VERSION 5.7 ;
  NOWIREEXTENSIONATPIN ON ;
  DIVIDERCHAR "/" ;
  BUSBITCHARS "[]" ;
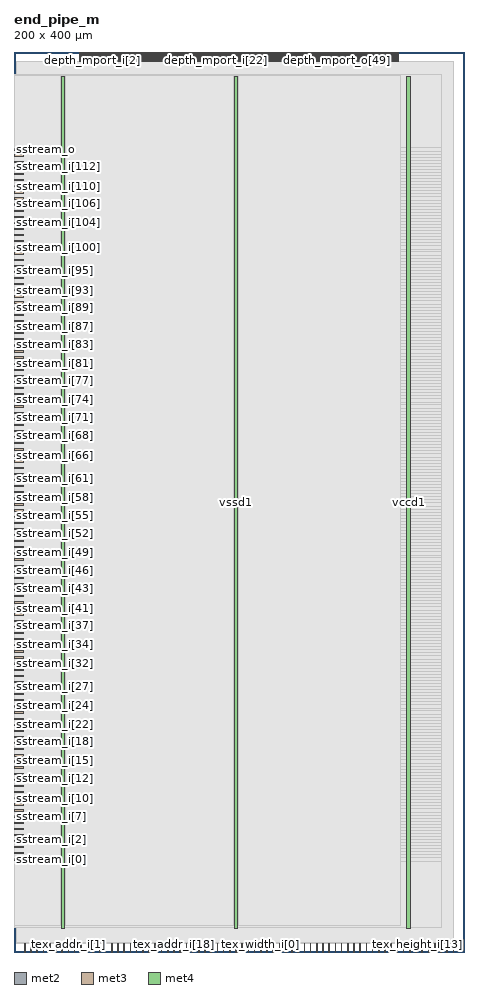
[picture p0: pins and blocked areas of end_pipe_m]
MACRO end_pipe_m
  CLASS BLOCK ;
  FOREIGN end_pipe_m ;
  ORIGIN 0.000 0.000 ;
  SIZE 200.000 BY 400.000 ;
  PIN busy_o
    DIRECTION OUTPUT TRISTATE ;
    USE SIGNAL ;
    ANTENNADIFFAREA 2.862000 ;
    PORT
      LAYER met2 ;
        RECT 15.730 0.000 16.010 4.000 ;
    END
  END busy_o
  PIN clk_i
    DIRECTION INPUT ;
    USE SIGNAL ;
    ANTENNAGATEAREA 0.852000 ;
    PORT
      LAYER met2 ;
        RECT 4.690 0.000 4.970 4.000 ;
    END
  END clk_i
  PIN depth_mport_i[0]
    DIRECTION INPUT ;
    USE SIGNAL ;
    ANTENNAGATEAREA 0.247500 ;
    PORT
      LAYER met2 ;
        RECT 29.070 396.000 29.350 400.000 ;
    END
  END depth_mport_i[0]
  PIN depth_mport_i[10]
    DIRECTION INPUT ;
    USE SIGNAL ;
    ANTENNAGATEAREA 0.495000 ;
    PORT
      LAYER met2 ;
        RECT 56.670 396.000 56.950 400.000 ;
    END
  END depth_mport_i[10]
  PIN depth_mport_i[11]
    DIRECTION INPUT ;
    USE SIGNAL ;
    ANTENNAGATEAREA 0.495000 ;
    PORT
      LAYER met2 ;
        RECT 59.430 396.000 59.710 400.000 ;
    END
  END depth_mport_i[11]
  PIN depth_mport_i[12]
    DIRECTION INPUT ;
    USE SIGNAL ;
    ANTENNAGATEAREA 0.495000 ;
    PORT
      LAYER met2 ;
        RECT 62.190 396.000 62.470 400.000 ;
    END
  END depth_mport_i[12]
  PIN depth_mport_i[13]
    DIRECTION INPUT ;
    USE SIGNAL ;
    ANTENNAGATEAREA 0.495000 ;
    PORT
      LAYER met2 ;
        RECT 64.950 396.000 65.230 400.000 ;
    END
  END depth_mport_i[13]
  PIN depth_mport_i[14]
    DIRECTION INPUT ;
    USE SIGNAL ;
    ANTENNAGATEAREA 0.495000 ;
    PORT
      LAYER met2 ;
        RECT 67.710 396.000 67.990 400.000 ;
    END
  END depth_mport_i[14]
  PIN depth_mport_i[15]
    DIRECTION INPUT ;
    USE SIGNAL ;
    ANTENNAGATEAREA 0.373500 ;
    PORT
      LAYER met2 ;
        RECT 70.470 396.000 70.750 400.000 ;
    END
  END depth_mport_i[15]
  PIN depth_mport_i[16]
    DIRECTION INPUT ;
    USE SIGNAL ;
    ANTENNAGATEAREA 0.495000 ;
    PORT
      LAYER met2 ;
        RECT 73.230 396.000 73.510 400.000 ;
    END
  END depth_mport_i[16]
  PIN depth_mport_i[17]
    DIRECTION INPUT ;
    USE SIGNAL ;
    ANTENNAGATEAREA 0.742500 ;
    PORT
      LAYER met2 ;
        RECT 75.990 396.000 76.270 400.000 ;
    END
  END depth_mport_i[17]
  PIN depth_mport_i[18]
    DIRECTION INPUT ;
    USE SIGNAL ;
    ANTENNAGATEAREA 0.742500 ;
    PORT
      LAYER met2 ;
        RECT 78.750 396.000 79.030 400.000 ;
    END
  END depth_mport_i[18]
  PIN depth_mport_i[19]
    DIRECTION INPUT ;
    USE SIGNAL ;
    ANTENNAGATEAREA 0.495000 ;
    PORT
      LAYER met2 ;
        RECT 81.510 396.000 81.790 400.000 ;
    END
  END depth_mport_i[19]
  PIN depth_mport_i[1]
    DIRECTION INPUT ;
    USE SIGNAL ;
    ANTENNAGATEAREA 0.373500 ;
    PORT
      LAYER met2 ;
        RECT 31.830 396.000 32.110 400.000 ;
    END
  END depth_mport_i[1]
  PIN depth_mport_i[20]
    DIRECTION INPUT ;
    USE SIGNAL ;
    ANTENNAGATEAREA 0.495000 ;
    PORT
      LAYER met2 ;
        RECT 84.270 396.000 84.550 400.000 ;
    END
  END depth_mport_i[20]
  PIN depth_mport_i[21]
    DIRECTION INPUT ;
    USE SIGNAL ;
    ANTENNAGATEAREA 0.495000 ;
    PORT
      LAYER met2 ;
        RECT 87.030 396.000 87.310 400.000 ;
    END
  END depth_mport_i[21]
  PIN depth_mport_i[22]
    DIRECTION INPUT ;
    USE SIGNAL ;
    ANTENNAGATEAREA 0.495000 ;
    PORT
      LAYER met2 ;
        RECT 89.790 396.000 90.070 400.000 ;
    END
  END depth_mport_i[22]
  PIN depth_mport_i[23]
    DIRECTION INPUT ;
    USE SIGNAL ;
    ANTENNAGATEAREA 0.495000 ;
    PORT
      LAYER met2 ;
        RECT 92.550 396.000 92.830 400.000 ;
    END
  END depth_mport_i[23]
  PIN depth_mport_i[24]
    DIRECTION INPUT ;
    USE SIGNAL ;
    ANTENNAGATEAREA 0.373500 ;
    PORT
      LAYER met2 ;
        RECT 95.310 396.000 95.590 400.000 ;
    END
  END depth_mport_i[24]
  PIN depth_mport_i[25]
    DIRECTION INPUT ;
    USE SIGNAL ;
    ANTENNAGATEAREA 0.495000 ;
    PORT
      LAYER met2 ;
        RECT 98.070 396.000 98.350 400.000 ;
    END
  END depth_mport_i[25]
  PIN depth_mport_i[26]
    DIRECTION INPUT ;
    USE SIGNAL ;
    ANTENNAGATEAREA 0.495000 ;
    PORT
      LAYER met2 ;
        RECT 100.830 396.000 101.110 400.000 ;
    END
  END depth_mport_i[26]
  PIN depth_mport_i[27]
    DIRECTION INPUT ;
    USE SIGNAL ;
    ANTENNAGATEAREA 0.495000 ;
    PORT
      LAYER met2 ;
        RECT 103.590 396.000 103.870 400.000 ;
    END
  END depth_mport_i[27]
  PIN depth_mport_i[28]
    DIRECTION INPUT ;
    USE SIGNAL ;
    ANTENNAGATEAREA 0.373500 ;
    PORT
      LAYER met2 ;
        RECT 106.350 396.000 106.630 400.000 ;
    END
  END depth_mport_i[28]
  PIN depth_mport_i[29]
    DIRECTION INPUT ;
    USE SIGNAL ;
    ANTENNAGATEAREA 0.990000 ;
    PORT
      LAYER met2 ;
        RECT 109.110 396.000 109.390 400.000 ;
    END
  END depth_mport_i[29]
  PIN depth_mport_i[2]
    DIRECTION INPUT ;
    USE SIGNAL ;
    ANTENNAGATEAREA 0.495000 ;
    PORT
      LAYER met2 ;
        RECT 34.590 396.000 34.870 400.000 ;
    END
  END depth_mport_i[2]
  PIN depth_mport_i[30]
    DIRECTION INPUT ;
    USE SIGNAL ;
    ANTENNAGATEAREA 0.990000 ;
    PORT
      LAYER met2 ;
        RECT 111.870 396.000 112.150 400.000 ;
    END
  END depth_mport_i[30]
  PIN depth_mport_i[31]
    DIRECTION INPUT ;
    USE SIGNAL ;
    ANTENNAGATEAREA 0.990000 ;
    PORT
      LAYER met2 ;
        RECT 114.630 396.000 114.910 400.000 ;
    END
  END depth_mport_i[31]
  PIN depth_mport_i[32]
    DIRECTION INPUT ;
    USE SIGNAL ;
    ANTENNAGATEAREA 0.742500 ;
    PORT
      LAYER met2 ;
        RECT 117.390 396.000 117.670 400.000 ;
    END
  END depth_mport_i[32]
  PIN depth_mport_i[33]
    DIRECTION INPUT ;
    USE SIGNAL ;
    PORT
      LAYER met2 ;
        RECT 120.150 396.000 120.430 400.000 ;
    END
  END depth_mport_i[33]
  PIN depth_mport_i[3]
    DIRECTION INPUT ;
    USE SIGNAL ;
    ANTENNAGATEAREA 0.495000 ;
    PORT
      LAYER met2 ;
        RECT 37.350 396.000 37.630 400.000 ;
    END
  END depth_mport_i[3]
  PIN depth_mport_i[4]
    DIRECTION INPUT ;
    USE SIGNAL ;
    ANTENNAGATEAREA 0.495000 ;
    PORT
      LAYER met2 ;
        RECT 40.110 396.000 40.390 400.000 ;
    END
  END depth_mport_i[4]
  PIN depth_mport_i[5]
    DIRECTION INPUT ;
    USE SIGNAL ;
    ANTENNAGATEAREA 0.495000 ;
    PORT
      LAYER met2 ;
        RECT 42.870 396.000 43.150 400.000 ;
    END
  END depth_mport_i[5]
  PIN depth_mport_i[6]
    DIRECTION INPUT ;
    USE SIGNAL ;
    ANTENNAGATEAREA 0.373500 ;
    PORT
      LAYER met2 ;
        RECT 45.630 396.000 45.910 400.000 ;
    END
  END depth_mport_i[6]
  PIN depth_mport_i[7]
    DIRECTION INPUT ;
    USE SIGNAL ;
    ANTENNAGATEAREA 0.495000 ;
    PORT
      LAYER met2 ;
        RECT 48.390 396.000 48.670 400.000 ;
    END
  END depth_mport_i[7]
  PIN depth_mport_i[8]
    DIRECTION INPUT ;
    USE SIGNAL ;
    ANTENNAGATEAREA 0.495000 ;
    PORT
      LAYER met2 ;
        RECT 51.150 396.000 51.430 400.000 ;
    END
  END depth_mport_i[8]
  PIN depth_mport_i[9]
    DIRECTION INPUT ;
    USE SIGNAL ;
    ANTENNAGATEAREA 0.495000 ;
    PORT
      LAYER met2 ;
        RECT 53.910 396.000 54.190 400.000 ;
    END
  END depth_mport_i[9]
  PIN depth_mport_o[0]
    DIRECTION OUTPUT TRISTATE ;
    USE SIGNAL ;
    ANTENNAGATEAREA 0.126000 ;
    ANTENNADIFFAREA 0.891000 ;
    PORT
      LAYER met2 ;
        RECT 29.530 396.000 29.810 400.000 ;
    END
  END depth_mport_o[0]
  PIN depth_mport_o[10]
    DIRECTION OUTPUT TRISTATE ;
    USE SIGNAL ;
    ANTENNAGATEAREA 0.126000 ;
    ANTENNADIFFAREA 0.891000 ;
    PORT
      LAYER met2 ;
        RECT 57.130 396.000 57.410 400.000 ;
    END
  END depth_mport_o[10]
  PIN depth_mport_o[11]
    DIRECTION OUTPUT TRISTATE ;
    USE SIGNAL ;
    ANTENNAGATEAREA 0.126000 ;
    ANTENNADIFFAREA 0.891000 ;
    PORT
      LAYER met2 ;
        RECT 59.890 396.000 60.170 400.000 ;
    END
  END depth_mport_o[11]
  PIN depth_mport_o[12]
    DIRECTION OUTPUT TRISTATE ;
    USE SIGNAL ;
    ANTENNAGATEAREA 0.126000 ;
    ANTENNADIFFAREA 0.891000 ;
    PORT
      LAYER met2 ;
        RECT 62.650 396.000 62.930 400.000 ;
    END
  END depth_mport_o[12]
  PIN depth_mport_o[13]
    DIRECTION OUTPUT TRISTATE ;
    USE SIGNAL ;
    ANTENNAGATEAREA 0.126000 ;
    ANTENNADIFFAREA 0.891000 ;
    PORT
      LAYER met2 ;
        RECT 65.410 396.000 65.690 400.000 ;
    END
  END depth_mport_o[13]
  PIN depth_mport_o[14]
    DIRECTION OUTPUT TRISTATE ;
    USE SIGNAL ;
    ANTENNAGATEAREA 0.126000 ;
    ANTENNADIFFAREA 0.891000 ;
    PORT
      LAYER met2 ;
        RECT 68.170 396.000 68.450 400.000 ;
    END
  END depth_mport_o[14]
  PIN depth_mport_o[15]
    DIRECTION OUTPUT TRISTATE ;
    USE SIGNAL ;
    ANTENNAGATEAREA 0.126000 ;
    ANTENNADIFFAREA 0.891000 ;
    PORT
      LAYER met2 ;
        RECT 70.930 396.000 71.210 400.000 ;
    END
  END depth_mport_o[15]
  PIN depth_mport_o[16]
    DIRECTION OUTPUT TRISTATE ;
    USE SIGNAL ;
    ANTENNAGATEAREA 0.126000 ;
    ANTENNADIFFAREA 0.891000 ;
    PORT
      LAYER met2 ;
        RECT 73.690 396.000 73.970 400.000 ;
    END
  END depth_mport_o[16]
  PIN depth_mport_o[17]
    DIRECTION OUTPUT TRISTATE ;
    USE SIGNAL ;
    ANTENNAGATEAREA 0.126000 ;
    ANTENNADIFFAREA 0.891000 ;
    PORT
      LAYER met2 ;
        RECT 76.450 396.000 76.730 400.000 ;
    END
  END depth_mport_o[17]
  PIN depth_mport_o[18]
    DIRECTION OUTPUT TRISTATE ;
    USE SIGNAL ;
    ANTENNAGATEAREA 0.126000 ;
    ANTENNADIFFAREA 0.891000 ;
    PORT
      LAYER met2 ;
        RECT 79.210 396.000 79.490 400.000 ;
    END
  END depth_mport_o[18]
  PIN depth_mport_o[19]
    DIRECTION OUTPUT TRISTATE ;
    USE SIGNAL ;
    ANTENNAGATEAREA 0.126000 ;
    ANTENNADIFFAREA 0.891000 ;
    PORT
      LAYER met2 ;
        RECT 81.970 396.000 82.250 400.000 ;
    END
  END depth_mport_o[19]
  PIN depth_mport_o[1]
    DIRECTION OUTPUT TRISTATE ;
    USE SIGNAL ;
    ANTENNAGATEAREA 0.126000 ;
    ANTENNADIFFAREA 0.891000 ;
    PORT
      LAYER met2 ;
        RECT 32.290 396.000 32.570 400.000 ;
    END
  END depth_mport_o[1]
  PIN depth_mport_o[20]
    DIRECTION OUTPUT TRISTATE ;
    USE SIGNAL ;
    ANTENNAGATEAREA 0.126000 ;
    ANTENNADIFFAREA 0.891000 ;
    PORT
      LAYER met2 ;
        RECT 84.730 396.000 85.010 400.000 ;
    END
  END depth_mport_o[20]
  PIN depth_mport_o[21]
    DIRECTION OUTPUT TRISTATE ;
    USE SIGNAL ;
    ANTENNAGATEAREA 0.126000 ;
    ANTENNADIFFAREA 0.891000 ;
    PORT
      LAYER met2 ;
        RECT 87.490 396.000 87.770 400.000 ;
    END
  END depth_mport_o[21]
  PIN depth_mport_o[22]
    DIRECTION OUTPUT TRISTATE ;
    USE SIGNAL ;
    ANTENNAGATEAREA 0.126000 ;
    ANTENNADIFFAREA 0.891000 ;
    PORT
      LAYER met2 ;
        RECT 90.250 396.000 90.530 400.000 ;
    END
  END depth_mport_o[22]
  PIN depth_mport_o[23]
    DIRECTION OUTPUT TRISTATE ;
    USE SIGNAL ;
    ANTENNAGATEAREA 0.126000 ;
    ANTENNADIFFAREA 0.891000 ;
    PORT
      LAYER met2 ;
        RECT 93.010 396.000 93.290 400.000 ;
    END
  END depth_mport_o[23]
  PIN depth_mport_o[24]
    DIRECTION OUTPUT TRISTATE ;
    USE SIGNAL ;
    ANTENNAGATEAREA 0.126000 ;
    ANTENNADIFFAREA 0.891000 ;
    PORT
      LAYER met2 ;
        RECT 95.770 396.000 96.050 400.000 ;
    END
  END depth_mport_o[24]
  PIN depth_mport_o[25]
    DIRECTION OUTPUT TRISTATE ;
    USE SIGNAL ;
    ANTENNAGATEAREA 0.126000 ;
    ANTENNADIFFAREA 0.891000 ;
    PORT
      LAYER met2 ;
        RECT 98.530 396.000 98.810 400.000 ;
    END
  END depth_mport_o[25]
  PIN depth_mport_o[26]
    DIRECTION OUTPUT TRISTATE ;
    USE SIGNAL ;
    ANTENNAGATEAREA 0.126000 ;
    ANTENNADIFFAREA 0.891000 ;
    PORT
      LAYER met2 ;
        RECT 101.290 396.000 101.570 400.000 ;
    END
  END depth_mport_o[26]
  PIN depth_mport_o[27]
    DIRECTION OUTPUT TRISTATE ;
    USE SIGNAL ;
    ANTENNAGATEAREA 0.126000 ;
    ANTENNADIFFAREA 0.891000 ;
    PORT
      LAYER met2 ;
        RECT 104.050 396.000 104.330 400.000 ;
    END
  END depth_mport_o[27]
  PIN depth_mport_o[28]
    DIRECTION OUTPUT TRISTATE ;
    USE SIGNAL ;
    ANTENNAGATEAREA 0.126000 ;
    ANTENNADIFFAREA 0.891000 ;
    PORT
      LAYER met2 ;
        RECT 106.810 396.000 107.090 400.000 ;
    END
  END depth_mport_o[28]
  PIN depth_mport_o[29]
    DIRECTION OUTPUT TRISTATE ;
    USE SIGNAL ;
    ANTENNAGATEAREA 0.126000 ;
    ANTENNADIFFAREA 0.891000 ;
    PORT
      LAYER met2 ;
        RECT 109.570 396.000 109.850 400.000 ;
    END
  END depth_mport_o[29]
  PIN depth_mport_o[2]
    DIRECTION OUTPUT TRISTATE ;
    USE SIGNAL ;
    ANTENNAGATEAREA 0.126000 ;
    ANTENNADIFFAREA 0.891000 ;
    PORT
      LAYER met2 ;
        RECT 35.050 396.000 35.330 400.000 ;
    END
  END depth_mport_o[2]
  PIN depth_mport_o[30]
    DIRECTION OUTPUT TRISTATE ;
    USE SIGNAL ;
    ANTENNAGATEAREA 0.126000 ;
    ANTENNADIFFAREA 0.891000 ;
    PORT
      LAYER met2 ;
        RECT 112.330 396.000 112.610 400.000 ;
    END
  END depth_mport_o[30]
  PIN depth_mport_o[31]
    DIRECTION OUTPUT TRISTATE ;
    USE SIGNAL ;
    ANTENNAGATEAREA 0.126000 ;
    ANTENNADIFFAREA 0.891000 ;
    PORT
      LAYER met2 ;
        RECT 115.090 396.000 115.370 400.000 ;
    END
  END depth_mport_o[31]
  PIN depth_mport_o[32]
    DIRECTION OUTPUT TRISTATE ;
    USE SIGNAL ;
    PORT
      LAYER met2 ;
        RECT 117.850 396.000 118.130 400.000 ;
    END
  END depth_mport_o[32]
  PIN depth_mport_o[33]
    DIRECTION OUTPUT TRISTATE ;
    USE SIGNAL ;
    PORT
      LAYER met2 ;
        RECT 120.610 396.000 120.890 400.000 ;
    END
  END depth_mport_o[33]
  PIN depth_mport_o[34]
    DIRECTION OUTPUT TRISTATE ;
    USE SIGNAL ;
    ANTENNAGATEAREA 0.126000 ;
    ANTENNADIFFAREA 0.891000 ;
    PORT
      LAYER met2 ;
        RECT 122.910 396.000 123.190 400.000 ;
    END
  END depth_mport_o[34]
  PIN depth_mport_o[35]
    DIRECTION OUTPUT TRISTATE ;
    USE SIGNAL ;
    ANTENNAGATEAREA 0.126000 ;
    ANTENNADIFFAREA 0.891000 ;
    PORT
      LAYER met2 ;
        RECT 124.290 396.000 124.570 400.000 ;
    END
  END depth_mport_o[35]
  PIN depth_mport_o[36]
    DIRECTION OUTPUT TRISTATE ;
    USE SIGNAL ;
    ANTENNAGATEAREA 0.126000 ;
    ANTENNADIFFAREA 0.891000 ;
    PORT
      LAYER met2 ;
        RECT 125.670 396.000 125.950 400.000 ;
    END
  END depth_mport_o[36]
  PIN depth_mport_o[37]
    DIRECTION OUTPUT TRISTATE ;
    USE SIGNAL ;
    ANTENNAGATEAREA 0.126000 ;
    ANTENNADIFFAREA 0.891000 ;
    PORT
      LAYER met2 ;
        RECT 127.050 396.000 127.330 400.000 ;
    END
  END depth_mport_o[37]
  PIN depth_mport_o[38]
    DIRECTION OUTPUT TRISTATE ;
    USE SIGNAL ;
    ANTENNAGATEAREA 0.126000 ;
    ANTENNADIFFAREA 0.891000 ;
    PORT
      LAYER met2 ;
        RECT 128.430 396.000 128.710 400.000 ;
    END
  END depth_mport_o[38]
  PIN depth_mport_o[39]
    DIRECTION OUTPUT TRISTATE ;
    USE SIGNAL ;
    ANTENNAGATEAREA 0.126000 ;
    ANTENNADIFFAREA 0.891000 ;
    PORT
      LAYER met2 ;
        RECT 129.810 396.000 130.090 400.000 ;
    END
  END depth_mport_o[39]
  PIN depth_mport_o[3]
    DIRECTION OUTPUT TRISTATE ;
    USE SIGNAL ;
    ANTENNAGATEAREA 0.126000 ;
    ANTENNADIFFAREA 0.891000 ;
    PORT
      LAYER met2 ;
        RECT 37.810 396.000 38.090 400.000 ;
    END
  END depth_mport_o[3]
  PIN depth_mport_o[40]
    DIRECTION OUTPUT TRISTATE ;
    USE SIGNAL ;
    ANTENNAGATEAREA 0.247500 ;
    ANTENNADIFFAREA 0.891000 ;
    PORT
      LAYER met2 ;
        RECT 131.190 396.000 131.470 400.000 ;
    END
  END depth_mport_o[40]
  PIN depth_mport_o[41]
    DIRECTION OUTPUT TRISTATE ;
    USE SIGNAL ;
    ANTENNAGATEAREA 0.247500 ;
    ANTENNADIFFAREA 0.891000 ;
    PORT
      LAYER met2 ;
        RECT 132.570 396.000 132.850 400.000 ;
    END
  END depth_mport_o[41]
  PIN depth_mport_o[42]
    DIRECTION OUTPUT TRISTATE ;
    USE SIGNAL ;
    ANTENNAGATEAREA 0.247500 ;
    ANTENNADIFFAREA 0.891000 ;
    PORT
      LAYER met2 ;
        RECT 133.950 396.000 134.230 400.000 ;
    END
  END depth_mport_o[42]
  PIN depth_mport_o[43]
    DIRECTION OUTPUT TRISTATE ;
    USE SIGNAL ;
    ANTENNAGATEAREA 0.247500 ;
    ANTENNADIFFAREA 0.891000 ;
    PORT
      LAYER met2 ;
        RECT 135.330 396.000 135.610 400.000 ;
    END
  END depth_mport_o[43]
  PIN depth_mport_o[44]
    DIRECTION OUTPUT TRISTATE ;
    USE SIGNAL ;
    ANTENNAGATEAREA 0.126000 ;
    ANTENNADIFFAREA 0.891000 ;
    PORT
      LAYER met2 ;
        RECT 136.710 396.000 136.990 400.000 ;
    END
  END depth_mport_o[44]
  PIN depth_mport_o[45]
    DIRECTION OUTPUT TRISTATE ;
    USE SIGNAL ;
    ANTENNAGATEAREA 0.247500 ;
    ANTENNADIFFAREA 0.891000 ;
    PORT
      LAYER met2 ;
        RECT 138.090 396.000 138.370 400.000 ;
    END
  END depth_mport_o[45]
  PIN depth_mport_o[46]
    DIRECTION OUTPUT TRISTATE ;
    USE SIGNAL ;
    ANTENNAGATEAREA 0.247500 ;
    ANTENNADIFFAREA 0.891000 ;
    PORT
      LAYER met2 ;
        RECT 139.470 396.000 139.750 400.000 ;
    END
  END depth_mport_o[46]
  PIN depth_mport_o[47]
    DIRECTION OUTPUT TRISTATE ;
    USE SIGNAL ;
    ANTENNAGATEAREA 0.247500 ;
    ANTENNADIFFAREA 0.891000 ;
    PORT
      LAYER met2 ;
        RECT 140.850 396.000 141.130 400.000 ;
    END
  END depth_mport_o[47]
  PIN depth_mport_o[48]
    DIRECTION OUTPUT TRISTATE ;
    USE SIGNAL ;
    ANTENNAGATEAREA 0.247500 ;
    ANTENNADIFFAREA 0.891000 ;
    PORT
      LAYER met2 ;
        RECT 142.230 396.000 142.510 400.000 ;
    END
  END depth_mport_o[48]
  PIN depth_mport_o[49]
    DIRECTION OUTPUT TRISTATE ;
    USE SIGNAL ;
    ANTENNAGATEAREA 0.247500 ;
    ANTENNADIFFAREA 0.891000 ;
    PORT
      LAYER met2 ;
        RECT 143.610 396.000 143.890 400.000 ;
    END
  END depth_mport_o[49]
  PIN depth_mport_o[4]
    DIRECTION OUTPUT TRISTATE ;
    USE SIGNAL ;
    ANTENNAGATEAREA 0.126000 ;
    ANTENNADIFFAREA 0.891000 ;
    PORT
      LAYER met2 ;
        RECT 40.570 396.000 40.850 400.000 ;
    END
  END depth_mport_o[4]
  PIN depth_mport_o[50]
    DIRECTION OUTPUT TRISTATE ;
    USE SIGNAL ;
    ANTENNAGATEAREA 0.247500 ;
    ANTENNADIFFAREA 0.891000 ;
    PORT
      LAYER met2 ;
        RECT 144.990 396.000 145.270 400.000 ;
    END
  END depth_mport_o[50]
  PIN depth_mport_o[51]
    DIRECTION OUTPUT TRISTATE ;
    USE SIGNAL ;
    ANTENNAGATEAREA 0.126000 ;
    ANTENNADIFFAREA 0.891000 ;
    PORT
      LAYER met2 ;
        RECT 146.370 396.000 146.650 400.000 ;
    END
  END depth_mport_o[51]
  PIN depth_mport_o[52]
    DIRECTION OUTPUT TRISTATE ;
    USE SIGNAL ;
    ANTENNAGATEAREA 0.126000 ;
    ANTENNADIFFAREA 0.891000 ;
    PORT
      LAYER met2 ;
        RECT 147.750 396.000 148.030 400.000 ;
    END
  END depth_mport_o[52]
  PIN depth_mport_o[53]
    DIRECTION OUTPUT TRISTATE ;
    USE SIGNAL ;
    ANTENNAGATEAREA 0.126000 ;
    ANTENNADIFFAREA 0.891000 ;
    PORT
      LAYER met2 ;
        RECT 149.130 396.000 149.410 400.000 ;
    END
  END depth_mport_o[53]
  PIN depth_mport_o[54]
    DIRECTION OUTPUT TRISTATE ;
    USE SIGNAL ;
    PORT
      LAYER met2 ;
        RECT 150.510 396.000 150.790 400.000 ;
    END
  END depth_mport_o[54]
  PIN depth_mport_o[55]
    DIRECTION OUTPUT TRISTATE ;
    USE SIGNAL ;
    PORT
      LAYER met2 ;
        RECT 151.890 396.000 152.170 400.000 ;
    END
  END depth_mport_o[55]
  PIN depth_mport_o[56]
    DIRECTION OUTPUT TRISTATE ;
    USE SIGNAL ;
    PORT
      LAYER met2 ;
        RECT 153.270 396.000 153.550 400.000 ;
    END
  END depth_mport_o[56]
  PIN depth_mport_o[57]
    DIRECTION OUTPUT TRISTATE ;
    USE SIGNAL ;
    PORT
      LAYER met2 ;
        RECT 154.650 396.000 154.930 400.000 ;
    END
  END depth_mport_o[57]
  PIN depth_mport_o[58]
    DIRECTION OUTPUT TRISTATE ;
    USE SIGNAL ;
    PORT
      LAYER met2 ;
        RECT 156.030 396.000 156.310 400.000 ;
    END
  END depth_mport_o[58]
  PIN depth_mport_o[59]
    DIRECTION OUTPUT TRISTATE ;
    USE SIGNAL ;
    PORT
      LAYER met2 ;
        RECT 157.410 396.000 157.690 400.000 ;
    END
  END depth_mport_o[59]
  PIN depth_mport_o[5]
    DIRECTION OUTPUT TRISTATE ;
    USE SIGNAL ;
    ANTENNAGATEAREA 0.126000 ;
    ANTENNADIFFAREA 0.891000 ;
    PORT
      LAYER met2 ;
        RECT 43.330 396.000 43.610 400.000 ;
    END
  END depth_mport_o[5]
  PIN depth_mport_o[60]
    DIRECTION OUTPUT TRISTATE ;
    USE SIGNAL ;
    PORT
      LAYER met2 ;
        RECT 158.790 396.000 159.070 400.000 ;
    END
  END depth_mport_o[60]
  PIN depth_mport_o[61]
    DIRECTION OUTPUT TRISTATE ;
    USE SIGNAL ;
    PORT
      LAYER met2 ;
        RECT 160.170 396.000 160.450 400.000 ;
    END
  END depth_mport_o[61]
  PIN depth_mport_o[62]
    DIRECTION OUTPUT TRISTATE ;
    USE SIGNAL ;
    PORT
      LAYER met2 ;
        RECT 161.550 396.000 161.830 400.000 ;
    END
  END depth_mport_o[62]
  PIN depth_mport_o[63]
    DIRECTION OUTPUT TRISTATE ;
    USE SIGNAL ;
    PORT
      LAYER met2 ;
        RECT 162.930 396.000 163.210 400.000 ;
    END
  END depth_mport_o[63]
  PIN depth_mport_o[64]
    DIRECTION OUTPUT TRISTATE ;
    USE SIGNAL ;
    ANTENNAGATEAREA 0.247500 ;
    ANTENNADIFFAREA 0.891000 ;
    PORT
      LAYER met2 ;
        RECT 164.310 396.000 164.590 400.000 ;
    END
  END depth_mport_o[64]
  PIN depth_mport_o[65]
    DIRECTION OUTPUT TRISTATE ;
    USE SIGNAL ;
    PORT
      LAYER met2 ;
        RECT 165.690 396.000 165.970 400.000 ;
    END
  END depth_mport_o[65]
  PIN depth_mport_o[66]
    DIRECTION OUTPUT TRISTATE ;
    USE SIGNAL ;
    ANTENNAGATEAREA 0.126000 ;
    ANTENNADIFFAREA 0.891000 ;
    PORT
      LAYER met2 ;
        RECT 167.070 396.000 167.350 400.000 ;
    END
  END depth_mport_o[66]
  PIN depth_mport_o[67]
    DIRECTION OUTPUT TRISTATE ;
    USE SIGNAL ;
    PORT
      LAYER met2 ;
        RECT 168.450 396.000 168.730 400.000 ;
    END
  END depth_mport_o[67]
  PIN depth_mport_o[68]
    DIRECTION OUTPUT TRISTATE ;
    USE SIGNAL ;
    ANTENNAGATEAREA 0.126000 ;
    ANTENNADIFFAREA 0.891000 ;
    PORT
      LAYER met2 ;
        RECT 169.830 396.000 170.110 400.000 ;
    END
  END depth_mport_o[68]
  PIN depth_mport_o[6]
    DIRECTION OUTPUT TRISTATE ;
    USE SIGNAL ;
    ANTENNAGATEAREA 0.126000 ;
    ANTENNADIFFAREA 0.891000 ;
    PORT
      LAYER met2 ;
        RECT 46.090 396.000 46.370 400.000 ;
    END
  END depth_mport_o[6]
  PIN depth_mport_o[7]
    DIRECTION OUTPUT TRISTATE ;
    USE SIGNAL ;
    ANTENNAGATEAREA 0.126000 ;
    ANTENNADIFFAREA 0.891000 ;
    PORT
      LAYER met2 ;
        RECT 48.850 396.000 49.130 400.000 ;
    END
  END depth_mport_o[7]
  PIN depth_mport_o[8]
    DIRECTION OUTPUT TRISTATE ;
    USE SIGNAL ;
    ANTENNAGATEAREA 0.126000 ;
    ANTENNADIFFAREA 0.891000 ;
    PORT
      LAYER met2 ;
        RECT 51.610 396.000 51.890 400.000 ;
    END
  END depth_mport_o[8]
  PIN depth_mport_o[9]
    DIRECTION OUTPUT TRISTATE ;
    USE SIGNAL ;
    ANTENNAGATEAREA 0.126000 ;
    ANTENNADIFFAREA 0.891000 ;
    PORT
      LAYER met2 ;
        RECT 54.370 396.000 54.650 400.000 ;
    END
  END depth_mport_o[9]
  PIN fb_i
    DIRECTION INPUT ;
    USE SIGNAL ;
    ANTENNAGATEAREA 1.984500 ;
    PORT
      LAYER met2 ;
        RECT 18.490 0.000 18.770 4.000 ;
    END
  END fb_i
  PIN filt_depth_fly_o
    DIRECTION OUTPUT TRISTATE ;
    USE SIGNAL ;
    ANTENNAGATEAREA 0.373500 ;
    ANTENNADIFFAREA 1.358700 ;
    PORT
      LAYER met2 ;
        RECT 10.210 0.000 10.490 4.000 ;
    END
  END filt_depth_fly_o
  PIN nrst_i
    DIRECTION INPUT ;
    USE SIGNAL ;
    ANTENNAGATEAREA 2.307000 ;
    PORT
      LAYER met2 ;
        RECT 7.450 0.000 7.730 4.000 ;
    END
  END nrst_i
  PIN pix_mport_i[0]
    DIRECTION INPUT ;
    USE SIGNAL ;
    PORT
      LAYER met2 ;
        RECT 29.990 396.000 30.270 400.000 ;
    END
  END pix_mport_i[0]
  PIN pix_mport_i[10]
    DIRECTION INPUT ;
    USE SIGNAL ;
    PORT
      LAYER met2 ;
        RECT 57.590 396.000 57.870 400.000 ;
    END
  END pix_mport_i[10]
  PIN pix_mport_i[11]
    DIRECTION INPUT ;
    USE SIGNAL ;
    PORT
      LAYER met2 ;
        RECT 60.350 396.000 60.630 400.000 ;
    END
  END pix_mport_i[11]
  PIN pix_mport_i[12]
    DIRECTION INPUT ;
    USE SIGNAL ;
    PORT
      LAYER met2 ;
        RECT 63.110 396.000 63.390 400.000 ;
    END
  END pix_mport_i[12]
  PIN pix_mport_i[13]
    DIRECTION INPUT ;
    USE SIGNAL ;
    PORT
      LAYER met2 ;
        RECT 65.870 396.000 66.150 400.000 ;
    END
  END pix_mport_i[13]
  PIN pix_mport_i[14]
    DIRECTION INPUT ;
    USE SIGNAL ;
    PORT
      LAYER met2 ;
        RECT 68.630 396.000 68.910 400.000 ;
    END
  END pix_mport_i[14]
  PIN pix_mport_i[15]
    DIRECTION INPUT ;
    USE SIGNAL ;
    PORT
      LAYER met2 ;
        RECT 71.390 396.000 71.670 400.000 ;
    END
  END pix_mport_i[15]
  PIN pix_mport_i[16]
    DIRECTION INPUT ;
    USE SIGNAL ;
    PORT
      LAYER met2 ;
        RECT 74.150 396.000 74.430 400.000 ;
    END
  END pix_mport_i[16]
  PIN pix_mport_i[17]
    DIRECTION INPUT ;
    USE SIGNAL ;
    PORT
      LAYER met2 ;
        RECT 76.910 396.000 77.190 400.000 ;
    END
  END pix_mport_i[17]
  PIN pix_mport_i[18]
    DIRECTION INPUT ;
    USE SIGNAL ;
    PORT
      LAYER met2 ;
        RECT 79.670 396.000 79.950 400.000 ;
    END
  END pix_mport_i[18]
  PIN pix_mport_i[19]
    DIRECTION INPUT ;
    USE SIGNAL ;
    PORT
      LAYER met2 ;
        RECT 82.430 396.000 82.710 400.000 ;
    END
  END pix_mport_i[19]
  PIN pix_mport_i[1]
    DIRECTION INPUT ;
    USE SIGNAL ;
    PORT
      LAYER met2 ;
        RECT 32.750 396.000 33.030 400.000 ;
    END
  END pix_mport_i[1]
  PIN pix_mport_i[20]
    DIRECTION INPUT ;
    USE SIGNAL ;
    PORT
      LAYER met2 ;
        RECT 85.190 396.000 85.470 400.000 ;
    END
  END pix_mport_i[20]
  PIN pix_mport_i[21]
    DIRECTION INPUT ;
    USE SIGNAL ;
    PORT
      LAYER met2 ;
        RECT 87.950 396.000 88.230 400.000 ;
    END
  END pix_mport_i[21]
  PIN pix_mport_i[22]
    DIRECTION INPUT ;
    USE SIGNAL ;
    PORT
      LAYER met2 ;
        RECT 90.710 396.000 90.990 400.000 ;
    END
  END pix_mport_i[22]
  PIN pix_mport_i[23]
    DIRECTION INPUT ;
    USE SIGNAL ;
    PORT
      LAYER met2 ;
        RECT 93.470 396.000 93.750 400.000 ;
    END
  END pix_mport_i[23]
  PIN pix_mport_i[24]
    DIRECTION INPUT ;
    USE SIGNAL ;
    PORT
      LAYER met2 ;
        RECT 96.230 396.000 96.510 400.000 ;
    END
  END pix_mport_i[24]
  PIN pix_mport_i[25]
    DIRECTION INPUT ;
    USE SIGNAL ;
    PORT
      LAYER met2 ;
        RECT 98.990 396.000 99.270 400.000 ;
    END
  END pix_mport_i[25]
  PIN pix_mport_i[26]
    DIRECTION INPUT ;
    USE SIGNAL ;
    PORT
      LAYER met2 ;
        RECT 101.750 396.000 102.030 400.000 ;
    END
  END pix_mport_i[26]
  PIN pix_mport_i[27]
    DIRECTION INPUT ;
    USE SIGNAL ;
    PORT
      LAYER met2 ;
        RECT 104.510 396.000 104.790 400.000 ;
    END
  END pix_mport_i[27]
  PIN pix_mport_i[28]
    DIRECTION INPUT ;
    USE SIGNAL ;
    PORT
      LAYER met2 ;
        RECT 107.270 396.000 107.550 400.000 ;
    END
  END pix_mport_i[28]
  PIN pix_mport_i[29]
    DIRECTION INPUT ;
    USE SIGNAL ;
    PORT
      LAYER met2 ;
        RECT 110.030 396.000 110.310 400.000 ;
    END
  END pix_mport_i[29]
  PIN pix_mport_i[2]
    DIRECTION INPUT ;
    USE SIGNAL ;
    PORT
      LAYER met2 ;
        RECT 35.510 396.000 35.790 400.000 ;
    END
  END pix_mport_i[2]
  PIN pix_mport_i[30]
    DIRECTION INPUT ;
    USE SIGNAL ;
    PORT
      LAYER met2 ;
        RECT 112.790 396.000 113.070 400.000 ;
    END
  END pix_mport_i[30]
  PIN pix_mport_i[31]
    DIRECTION INPUT ;
    USE SIGNAL ;
    PORT
      LAYER met2 ;
        RECT 115.550 396.000 115.830 400.000 ;
    END
  END pix_mport_i[31]
  PIN pix_mport_i[32]
    DIRECTION INPUT ;
    USE SIGNAL ;
    ANTENNAGATEAREA 0.742500 ;
    PORT
      LAYER met2 ;
        RECT 118.310 396.000 118.590 400.000 ;
    END
  END pix_mport_i[32]
  PIN pix_mport_i[33]
    DIRECTION INPUT ;
    USE SIGNAL ;
    PORT
      LAYER met2 ;
        RECT 121.070 396.000 121.350 400.000 ;
    END
  END pix_mport_i[33]
  PIN pix_mport_i[3]
    DIRECTION INPUT ;
    USE SIGNAL ;
    PORT
      LAYER met2 ;
        RECT 38.270 396.000 38.550 400.000 ;
    END
  END pix_mport_i[3]
  PIN pix_mport_i[4]
    DIRECTION INPUT ;
    USE SIGNAL ;
    PORT
      LAYER met2 ;
        RECT 41.030 396.000 41.310 400.000 ;
    END
  END pix_mport_i[4]
  PIN pix_mport_i[5]
    DIRECTION INPUT ;
    USE SIGNAL ;
    PORT
      LAYER met2 ;
        RECT 43.790 396.000 44.070 400.000 ;
    END
  END pix_mport_i[5]
  PIN pix_mport_i[6]
    DIRECTION INPUT ;
    USE SIGNAL ;
    PORT
      LAYER met2 ;
        RECT 46.550 396.000 46.830 400.000 ;
    END
  END pix_mport_i[6]
  PIN pix_mport_i[7]
    DIRECTION INPUT ;
    USE SIGNAL ;
    PORT
      LAYER met2 ;
        RECT 49.310 396.000 49.590 400.000 ;
    END
  END pix_mport_i[7]
  PIN pix_mport_i[8]
    DIRECTION INPUT ;
    USE SIGNAL ;
    PORT
      LAYER met2 ;
        RECT 52.070 396.000 52.350 400.000 ;
    END
  END pix_mport_i[8]
  PIN pix_mport_i[9]
    DIRECTION INPUT ;
    USE SIGNAL ;
    PORT
      LAYER met2 ;
        RECT 54.830 396.000 55.110 400.000 ;
    END
  END pix_mport_i[9]
  PIN pix_mport_o[0]
    DIRECTION OUTPUT TRISTATE ;
    USE SIGNAL ;
    ANTENNAGATEAREA 0.126000 ;
    ANTENNADIFFAREA 0.891000 ;
    PORT
      LAYER met2 ;
        RECT 30.450 396.000 30.730 400.000 ;
    END
  END pix_mport_o[0]
  PIN pix_mport_o[10]
    DIRECTION OUTPUT TRISTATE ;
    USE SIGNAL ;
    PORT
      LAYER met2 ;
        RECT 58.050 396.000 58.330 400.000 ;
    END
  END pix_mport_o[10]
  PIN pix_mport_o[11]
    DIRECTION OUTPUT TRISTATE ;
    USE SIGNAL ;
    PORT
      LAYER met2 ;
        RECT 60.810 396.000 61.090 400.000 ;
    END
  END pix_mport_o[11]
  PIN pix_mport_o[12]
    DIRECTION OUTPUT TRISTATE ;
    USE SIGNAL ;
    PORT
      LAYER met2 ;
        RECT 63.570 396.000 63.850 400.000 ;
    END
  END pix_mport_o[12]
  PIN pix_mport_o[13]
    DIRECTION OUTPUT TRISTATE ;
    USE SIGNAL ;
    PORT
      LAYER met2 ;
        RECT 66.330 396.000 66.610 400.000 ;
    END
  END pix_mport_o[13]
  PIN pix_mport_o[14]
    DIRECTION OUTPUT TRISTATE ;
    USE SIGNAL ;
    PORT
      LAYER met2 ;
        RECT 69.090 396.000 69.370 400.000 ;
    END
  END pix_mport_o[14]
  PIN pix_mport_o[15]
    DIRECTION OUTPUT TRISTATE ;
    USE SIGNAL ;
    PORT
      LAYER met2 ;
        RECT 71.850 396.000 72.130 400.000 ;
    END
  END pix_mport_o[15]
  PIN pix_mport_o[16]
    DIRECTION OUTPUT TRISTATE ;
    USE SIGNAL ;
    PORT
      LAYER met2 ;
        RECT 74.610 396.000 74.890 400.000 ;
    END
  END pix_mport_o[16]
  PIN pix_mport_o[17]
    DIRECTION OUTPUT TRISTATE ;
    USE SIGNAL ;
    PORT
      LAYER met2 ;
        RECT 77.370 396.000 77.650 400.000 ;
    END
  END pix_mport_o[17]
  PIN pix_mport_o[18]
    DIRECTION OUTPUT TRISTATE ;
    USE SIGNAL ;
    PORT
      LAYER met2 ;
        RECT 80.130 396.000 80.410 400.000 ;
    END
  END pix_mport_o[18]
  PIN pix_mport_o[19]
    DIRECTION OUTPUT TRISTATE ;
    USE SIGNAL ;
    PORT
      LAYER met2 ;
        RECT 82.890 396.000 83.170 400.000 ;
    END
  END pix_mport_o[19]
  PIN pix_mport_o[1]
    DIRECTION OUTPUT TRISTATE ;
    USE SIGNAL ;
    ANTENNAGATEAREA 0.126000 ;
    ANTENNADIFFAREA 0.891000 ;
    PORT
      LAYER met2 ;
        RECT 33.210 396.000 33.490 400.000 ;
    END
  END pix_mport_o[1]
  PIN pix_mport_o[20]
    DIRECTION OUTPUT TRISTATE ;
    USE SIGNAL ;
    PORT
      LAYER met2 ;
        RECT 85.650 396.000 85.930 400.000 ;
    END
  END pix_mport_o[20]
  PIN pix_mport_o[21]
    DIRECTION OUTPUT TRISTATE ;
    USE SIGNAL ;
    PORT
      LAYER met2 ;
        RECT 88.410 396.000 88.690 400.000 ;
    END
  END pix_mport_o[21]
  PIN pix_mport_o[22]
    DIRECTION OUTPUT TRISTATE ;
    USE SIGNAL ;
    PORT
      LAYER met2 ;
        RECT 91.170 396.000 91.450 400.000 ;
    END
  END pix_mport_o[22]
  PIN pix_mport_o[23]
    DIRECTION OUTPUT TRISTATE ;
    USE SIGNAL ;
    PORT
      LAYER met2 ;
        RECT 93.930 396.000 94.210 400.000 ;
    END
  END pix_mport_o[23]
  PIN pix_mport_o[24]
    DIRECTION OUTPUT TRISTATE ;
    USE SIGNAL ;
    PORT
      LAYER met2 ;
        RECT 96.690 396.000 96.970 400.000 ;
    END
  END pix_mport_o[24]
  PIN pix_mport_o[25]
    DIRECTION OUTPUT TRISTATE ;
    USE SIGNAL ;
    PORT
      LAYER met2 ;
        RECT 99.450 396.000 99.730 400.000 ;
    END
  END pix_mport_o[25]
  PIN pix_mport_o[26]
    DIRECTION OUTPUT TRISTATE ;
    USE SIGNAL ;
    PORT
      LAYER met2 ;
        RECT 102.210 396.000 102.490 400.000 ;
    END
  END pix_mport_o[26]
  PIN pix_mport_o[27]
    DIRECTION OUTPUT TRISTATE ;
    USE SIGNAL ;
    PORT
      LAYER met2 ;
        RECT 104.970 396.000 105.250 400.000 ;
    END
  END pix_mport_o[27]
  PIN pix_mport_o[28]
    DIRECTION OUTPUT TRISTATE ;
    USE SIGNAL ;
    PORT
      LAYER met2 ;
        RECT 107.730 396.000 108.010 400.000 ;
    END
  END pix_mport_o[28]
  PIN pix_mport_o[29]
    DIRECTION OUTPUT TRISTATE ;
    USE SIGNAL ;
    PORT
      LAYER met2 ;
        RECT 110.490 396.000 110.770 400.000 ;
    END
  END pix_mport_o[29]
  PIN pix_mport_o[2]
    DIRECTION OUTPUT TRISTATE ;
    USE SIGNAL ;
    ANTENNAGATEAREA 0.126000 ;
    ANTENNADIFFAREA 0.891000 ;
    PORT
      LAYER met2 ;
        RECT 35.970 396.000 36.250 400.000 ;
    END
  END pix_mport_o[2]
  PIN pix_mport_o[30]
    DIRECTION OUTPUT TRISTATE ;
    USE SIGNAL ;
    PORT
      LAYER met2 ;
        RECT 113.250 396.000 113.530 400.000 ;
    END
  END pix_mport_o[30]
  PIN pix_mport_o[31]
    DIRECTION OUTPUT TRISTATE ;
    USE SIGNAL ;
    PORT
      LAYER met2 ;
        RECT 116.010 396.000 116.290 400.000 ;
    END
  END pix_mport_o[31]
  PIN pix_mport_o[32]
    DIRECTION OUTPUT TRISTATE ;
    USE SIGNAL ;
    ANTENNAGATEAREA 0.126000 ;
    ANTENNADIFFAREA 0.891000 ;
    PORT
      LAYER met2 ;
        RECT 118.770 396.000 119.050 400.000 ;
    END
  END pix_mport_o[32]
  PIN pix_mport_o[33]
    DIRECTION OUTPUT TRISTATE ;
    USE SIGNAL ;
    ANTENNAGATEAREA 0.126000 ;
    ANTENNADIFFAREA 0.891000 ;
    PORT
      LAYER met2 ;
        RECT 121.530 396.000 121.810 400.000 ;
    END
  END pix_mport_o[33]
  PIN pix_mport_o[34]
    DIRECTION OUTPUT TRISTATE ;
    USE SIGNAL ;
    ANTENNAGATEAREA 0.126000 ;
    ANTENNADIFFAREA 0.891000 ;
    PORT
      LAYER met2 ;
        RECT 123.370 396.000 123.650 400.000 ;
    END
  END pix_mport_o[34]
  PIN pix_mport_o[35]
    DIRECTION OUTPUT TRISTATE ;
    USE SIGNAL ;
    ANTENNAGATEAREA 0.126000 ;
    ANTENNADIFFAREA 0.891000 ;
    PORT
      LAYER met2 ;
        RECT 124.750 396.000 125.030 400.000 ;
    END
  END pix_mport_o[35]
  PIN pix_mport_o[36]
    DIRECTION OUTPUT TRISTATE ;
    USE SIGNAL ;
    ANTENNAGATEAREA 0.126000 ;
    ANTENNADIFFAREA 0.891000 ;
    PORT
      LAYER met2 ;
        RECT 126.130 396.000 126.410 400.000 ;
    END
  END pix_mport_o[36]
  PIN pix_mport_o[37]
    DIRECTION OUTPUT TRISTATE ;
    USE SIGNAL ;
    ANTENNAGATEAREA 0.126000 ;
    ANTENNADIFFAREA 0.891000 ;
    PORT
      LAYER met2 ;
        RECT 127.510 396.000 127.790 400.000 ;
    END
  END pix_mport_o[37]
  PIN pix_mport_o[38]
    DIRECTION OUTPUT TRISTATE ;
    USE SIGNAL ;
    ANTENNAGATEAREA 0.247500 ;
    ANTENNADIFFAREA 0.891000 ;
    PORT
      LAYER met2 ;
        RECT 128.890 396.000 129.170 400.000 ;
    END
  END pix_mport_o[38]
  PIN pix_mport_o[39]
    DIRECTION OUTPUT TRISTATE ;
    USE SIGNAL ;
    ANTENNAGATEAREA 0.126000 ;
    ANTENNADIFFAREA 0.891000 ;
    PORT
      LAYER met2 ;
        RECT 130.270 396.000 130.550 400.000 ;
    END
  END pix_mport_o[39]
  PIN pix_mport_o[3]
    DIRECTION OUTPUT TRISTATE ;
    USE SIGNAL ;
    ANTENNAGATEAREA 0.126000 ;
    ANTENNADIFFAREA 0.891000 ;
    PORT
      LAYER met2 ;
        RECT 38.730 396.000 39.010 400.000 ;
    END
  END pix_mport_o[3]
  PIN pix_mport_o[40]
    DIRECTION OUTPUT TRISTATE ;
    USE SIGNAL ;
    ANTENNAGATEAREA 0.247500 ;
    ANTENNADIFFAREA 0.891000 ;
    PORT
      LAYER met2 ;
        RECT 131.650 396.000 131.930 400.000 ;
    END
  END pix_mport_o[40]
  PIN pix_mport_o[41]
    DIRECTION OUTPUT TRISTATE ;
    USE SIGNAL ;
    ANTENNAGATEAREA 0.126000 ;
    ANTENNADIFFAREA 0.891000 ;
    PORT
      LAYER met2 ;
        RECT 133.030 396.000 133.310 400.000 ;
    END
  END pix_mport_o[41]
  PIN pix_mport_o[42]
    DIRECTION OUTPUT TRISTATE ;
    USE SIGNAL ;
    ANTENNAGATEAREA 0.247500 ;
    ANTENNADIFFAREA 0.891000 ;
    PORT
      LAYER met2 ;
        RECT 134.410 396.000 134.690 400.000 ;
    END
  END pix_mport_o[42]
  PIN pix_mport_o[43]
    DIRECTION OUTPUT TRISTATE ;
    USE SIGNAL ;
    ANTENNAGATEAREA 0.126000 ;
    ANTENNADIFFAREA 0.891000 ;
    PORT
      LAYER met2 ;
        RECT 135.790 396.000 136.070 400.000 ;
    END
  END pix_mport_o[43]
  PIN pix_mport_o[44]
    DIRECTION OUTPUT TRISTATE ;
    USE SIGNAL ;
    ANTENNAGATEAREA 0.247500 ;
    ANTENNADIFFAREA 0.891000 ;
    PORT
      LAYER met2 ;
        RECT 137.170 396.000 137.450 400.000 ;
    END
  END pix_mport_o[44]
  PIN pix_mport_o[45]
    DIRECTION OUTPUT TRISTATE ;
    USE SIGNAL ;
    ANTENNAGATEAREA 0.247500 ;
    ANTENNADIFFAREA 0.891000 ;
    PORT
      LAYER met2 ;
        RECT 138.550 396.000 138.830 400.000 ;
    END
  END pix_mport_o[45]
  PIN pix_mport_o[46]
    DIRECTION OUTPUT TRISTATE ;
    USE SIGNAL ;
    ANTENNAGATEAREA 0.247500 ;
    ANTENNADIFFAREA 0.891000 ;
    PORT
      LAYER met2 ;
        RECT 139.930 396.000 140.210 400.000 ;
    END
  END pix_mport_o[46]
  PIN pix_mport_o[47]
    DIRECTION OUTPUT TRISTATE ;
    USE SIGNAL ;
    ANTENNAGATEAREA 0.126000 ;
    ANTENNADIFFAREA 0.891000 ;
    PORT
      LAYER met2 ;
        RECT 141.310 396.000 141.590 400.000 ;
    END
  END pix_mport_o[47]
  PIN pix_mport_o[48]
    DIRECTION OUTPUT TRISTATE ;
    USE SIGNAL ;
    ANTENNAGATEAREA 0.126000 ;
    ANTENNADIFFAREA 0.891000 ;
    PORT
      LAYER met2 ;
        RECT 142.690 396.000 142.970 400.000 ;
    END
  END pix_mport_o[48]
  PIN pix_mport_o[49]
    DIRECTION OUTPUT TRISTATE ;
    USE SIGNAL ;
    ANTENNAGATEAREA 0.247500 ;
    ANTENNADIFFAREA 0.891000 ;
    PORT
      LAYER met2 ;
        RECT 144.070 396.000 144.350 400.000 ;
    END
  END pix_mport_o[49]
  PIN pix_mport_o[4]
    DIRECTION OUTPUT TRISTATE ;
    USE SIGNAL ;
    ANTENNAGATEAREA 0.126000 ;
    ANTENNADIFFAREA 0.891000 ;
    PORT
      LAYER met2 ;
        RECT 41.490 396.000 41.770 400.000 ;
    END
  END pix_mport_o[4]
  PIN pix_mport_o[50]
    DIRECTION OUTPUT TRISTATE ;
    USE SIGNAL ;
    ANTENNAGATEAREA 0.126000 ;
    ANTENNADIFFAREA 0.891000 ;
    PORT
      LAYER met2 ;
        RECT 145.450 396.000 145.730 400.000 ;
    END
  END pix_mport_o[50]
  PIN pix_mport_o[51]
    DIRECTION OUTPUT TRISTATE ;
    USE SIGNAL ;
    PORT
      LAYER met2 ;
        RECT 146.830 396.000 147.110 400.000 ;
    END
  END pix_mport_o[51]
  PIN pix_mport_o[52]
    DIRECTION OUTPUT TRISTATE ;
    USE SIGNAL ;
    PORT
      LAYER met2 ;
        RECT 148.210 396.000 148.490 400.000 ;
    END
  END pix_mport_o[52]
  PIN pix_mport_o[53]
    DIRECTION OUTPUT TRISTATE ;
    USE SIGNAL ;
    PORT
      LAYER met2 ;
        RECT 149.590 396.000 149.870 400.000 ;
    END
  END pix_mport_o[53]
  PIN pix_mport_o[54]
    DIRECTION OUTPUT TRISTATE ;
    USE SIGNAL ;
    PORT
      LAYER met2 ;
        RECT 150.970 396.000 151.250 400.000 ;
    END
  END pix_mport_o[54]
  PIN pix_mport_o[55]
    DIRECTION OUTPUT TRISTATE ;
    USE SIGNAL ;
    PORT
      LAYER met2 ;
        RECT 152.350 396.000 152.630 400.000 ;
    END
  END pix_mport_o[55]
  PIN pix_mport_o[56]
    DIRECTION OUTPUT TRISTATE ;
    USE SIGNAL ;
    PORT
      LAYER met2 ;
        RECT 153.730 396.000 154.010 400.000 ;
    END
  END pix_mport_o[56]
  PIN pix_mport_o[57]
    DIRECTION OUTPUT TRISTATE ;
    USE SIGNAL ;
    PORT
      LAYER met2 ;
        RECT 155.110 396.000 155.390 400.000 ;
    END
  END pix_mport_o[57]
  PIN pix_mport_o[58]
    DIRECTION OUTPUT TRISTATE ;
    USE SIGNAL ;
    PORT
      LAYER met2 ;
        RECT 156.490 396.000 156.770 400.000 ;
    END
  END pix_mport_o[58]
  PIN pix_mport_o[59]
    DIRECTION OUTPUT TRISTATE ;
    USE SIGNAL ;
    PORT
      LAYER met2 ;
        RECT 157.870 396.000 158.150 400.000 ;
    END
  END pix_mport_o[59]
  PIN pix_mport_o[5]
    DIRECTION OUTPUT TRISTATE ;
    USE SIGNAL ;
    ANTENNAGATEAREA 0.126000 ;
    ANTENNADIFFAREA 0.891000 ;
    PORT
      LAYER met2 ;
        RECT 44.250 396.000 44.530 400.000 ;
    END
  END pix_mport_o[5]
  PIN pix_mport_o[60]
    DIRECTION OUTPUT TRISTATE ;
    USE SIGNAL ;
    PORT
      LAYER met2 ;
        RECT 159.250 396.000 159.530 400.000 ;
    END
  END pix_mport_o[60]
  PIN pix_mport_o[61]
    DIRECTION OUTPUT TRISTATE ;
    USE SIGNAL ;
    PORT
      LAYER met2 ;
        RECT 160.630 396.000 160.910 400.000 ;
    END
  END pix_mport_o[61]
  PIN pix_mport_o[62]
    DIRECTION OUTPUT TRISTATE ;
    USE SIGNAL ;
    PORT
      LAYER met2 ;
        RECT 162.010 396.000 162.290 400.000 ;
    END
  END pix_mport_o[62]
  PIN pix_mport_o[63]
    DIRECTION OUTPUT TRISTATE ;
    USE SIGNAL ;
    PORT
      LAYER met2 ;
        RECT 163.390 396.000 163.670 400.000 ;
    END
  END pix_mport_o[63]
  PIN pix_mport_o[64]
    DIRECTION OUTPUT TRISTATE ;
    USE SIGNAL ;
    ANTENNAGATEAREA 0.126000 ;
    ANTENNADIFFAREA 0.891000 ;
    PORT
      LAYER met2 ;
        RECT 164.770 396.000 165.050 400.000 ;
    END
  END pix_mport_o[64]
  PIN pix_mport_o[65]
    DIRECTION OUTPUT TRISTATE ;
    USE SIGNAL ;
    PORT
      LAYER met2 ;
        RECT 166.150 396.000 166.430 400.000 ;
    END
  END pix_mport_o[65]
  PIN pix_mport_o[66]
    DIRECTION OUTPUT TRISTATE ;
    USE SIGNAL ;
    PORT
      LAYER met2 ;
        RECT 167.530 396.000 167.810 400.000 ;
    END
  END pix_mport_o[66]
  PIN pix_mport_o[67]
    DIRECTION OUTPUT TRISTATE ;
    USE SIGNAL ;
    PORT
      LAYER met2 ;
        RECT 168.910 396.000 169.190 400.000 ;
    END
  END pix_mport_o[67]
  PIN pix_mport_o[68]
    DIRECTION OUTPUT TRISTATE ;
    USE SIGNAL ;
    ANTENNAGATEAREA 0.126000 ;
    ANTENNADIFFAREA 0.891000 ;
    PORT
      LAYER met2 ;
        RECT 170.290 396.000 170.570 400.000 ;
    END
  END pix_mport_o[68]
  PIN pix_mport_o[6]
    DIRECTION OUTPUT TRISTATE ;
    USE SIGNAL ;
    ANTENNAGATEAREA 0.126000 ;
    ANTENNADIFFAREA 0.891000 ;
    PORT
      LAYER met2 ;
        RECT 47.010 396.000 47.290 400.000 ;
    END
  END pix_mport_o[6]
  PIN pix_mport_o[7]
    DIRECTION OUTPUT TRISTATE ;
    USE SIGNAL ;
    ANTENNAGATEAREA 0.126000 ;
    ANTENNADIFFAREA 0.891000 ;
    PORT
      LAYER met2 ;
        RECT 49.770 396.000 50.050 400.000 ;
    END
  END pix_mport_o[7]
  PIN pix_mport_o[8]
    DIRECTION OUTPUT TRISTATE ;
    USE SIGNAL ;
    PORT
      LAYER met2 ;
        RECT 52.530 396.000 52.810 400.000 ;
    END
  END pix_mport_o[8]
  PIN pix_mport_o[9]
    DIRECTION OUTPUT TRISTATE ;
    USE SIGNAL ;
    PORT
      LAYER met2 ;
        RECT 55.290 396.000 55.570 400.000 ;
    END
  END pix_mport_o[9]
  PIN sstream_i[0]
    DIRECTION INPUT ;
    USE SIGNAL ;
    ANTENNAGATEAREA 0.126000 ;
    ANTENNADIFFAREA 0.869400 ;
    PORT
      LAYER met3 ;
        RECT 0.000 40.840 4.000 41.440 ;
    END
  END sstream_i[0]
  PIN sstream_i[100]
    DIRECTION INPUT ;
    USE SIGNAL ;
    ANTENNAGATEAREA 0.126000 ;
    PORT
      LAYER met3 ;
        RECT 0.000 312.840 4.000 313.440 ;
    END
  END sstream_i[100]
  PIN sstream_i[101]
    DIRECTION INPUT ;
    USE SIGNAL ;
    ANTENNAGATEAREA 0.126000 ;
    PORT
      LAYER met3 ;
        RECT 0.000 315.560 4.000 316.160 ;
    END
  END sstream_i[101]
  PIN sstream_i[102]
    DIRECTION INPUT ;
    USE SIGNAL ;
    ANTENNAGATEAREA 0.126000 ;
    PORT
      LAYER met3 ;
        RECT 0.000 318.280 4.000 318.880 ;
    END
  END sstream_i[102]
  PIN sstream_i[103]
    DIRECTION INPUT ;
    USE SIGNAL ;
    ANTENNAGATEAREA 0.126000 ;
    PORT
      LAYER met3 ;
        RECT 0.000 321.000 4.000 321.600 ;
    END
  END sstream_i[103]
  PIN sstream_i[104]
    DIRECTION INPUT ;
    USE SIGNAL ;
    ANTENNAGATEAREA 0.126000 ;
    PORT
      LAYER met3 ;
        RECT 0.000 323.720 4.000 324.320 ;
    END
  END sstream_i[104]
  PIN sstream_i[105]
    DIRECTION INPUT ;
    USE SIGNAL ;
    ANTENNAGATEAREA 0.126000 ;
    PORT
      LAYER met3 ;
        RECT 0.000 326.440 4.000 327.040 ;
    END
  END sstream_i[105]
  PIN sstream_i[106]
    DIRECTION INPUT ;
    USE SIGNAL ;
    ANTENNAGATEAREA 0.126000 ;
    PORT
      LAYER met3 ;
        RECT 0.000 329.160 4.000 329.760 ;
    END
  END sstream_i[106]
  PIN sstream_i[107]
    DIRECTION INPUT ;
    USE SIGNAL ;
    ANTENNAGATEAREA 0.126000 ;
    PORT
      LAYER met3 ;
        RECT 0.000 331.880 4.000 332.480 ;
    END
  END sstream_i[107]
  PIN sstream_i[108]
    DIRECTION INPUT ;
    USE SIGNAL ;
    ANTENNAGATEAREA 0.126000 ;
    PORT
      LAYER met3 ;
        RECT 0.000 334.600 4.000 335.200 ;
    END
  END sstream_i[108]
  PIN sstream_i[109]
    DIRECTION INPUT ;
    USE SIGNAL ;
    ANTENNAGATEAREA 0.126000 ;
    PORT
      LAYER met3 ;
        RECT 0.000 337.320 4.000 337.920 ;
    END
  END sstream_i[109]
  PIN sstream_i[10]
    DIRECTION INPUT ;
    USE SIGNAL ;
    ANTENNAGATEAREA 0.126000 ;
    ANTENNADIFFAREA 3.477600 ;
    PORT
      LAYER met3 ;
        RECT 0.000 68.040 4.000 68.640 ;
    END
  END sstream_i[10]
  PIN sstream_i[110]
    DIRECTION INPUT ;
    USE SIGNAL ;
    ANTENNAGATEAREA 0.126000 ;
    PORT
      LAYER met3 ;
        RECT 0.000 340.040 4.000 340.640 ;
    END
  END sstream_i[110]
  PIN sstream_i[111]
    DIRECTION INPUT ;
    USE SIGNAL ;
    ANTENNAGATEAREA 0.126000 ;
    ANTENNADIFFAREA 0.434700 ;
    PORT
      LAYER met3 ;
        RECT 0.000 342.760 4.000 343.360 ;
    END
  END sstream_i[111]
  PIN sstream_i[112]
    DIRECTION INPUT ;
    USE SIGNAL ;
    ANTENNAGATEAREA 0.126000 ;
    PORT
      LAYER met3 ;
        RECT 0.000 345.480 4.000 346.080 ;
    END
  END sstream_i[112]
  PIN sstream_i[113]
    DIRECTION INPUT ;
    USE SIGNAL ;
    ANTENNAGATEAREA 0.126000 ;
    PORT
      LAYER met3 ;
        RECT 0.000 348.200 4.000 348.800 ;
    END
  END sstream_i[113]
  PIN sstream_i[114]
    DIRECTION INPUT ;
    USE SIGNAL ;
    ANTENNAGATEAREA 0.621000 ;
    PORT
      LAYER met3 ;
        RECT 0.000 350.920 4.000 351.520 ;
    END
  END sstream_i[114]
  PIN sstream_i[115]
    DIRECTION INPUT ;
    USE SIGNAL ;
    PORT
      LAYER met3 ;
        RECT 0.000 353.640 4.000 354.240 ;
    END
  END sstream_i[115]
  PIN sstream_i[11]
    DIRECTION INPUT ;
    USE SIGNAL ;
    ANTENNAGATEAREA 0.126000 ;
    ANTENNADIFFAREA 3.042900 ;
    PORT
      LAYER met3 ;
        RECT 0.000 70.760 4.000 71.360 ;
    END
  END sstream_i[11]
  PIN sstream_i[12]
    DIRECTION INPUT ;
    USE SIGNAL ;
    ANTENNAGATEAREA 0.126000 ;
    ANTENNADIFFAREA 2.608200 ;
    PORT
      LAYER met3 ;
        RECT 0.000 73.480 4.000 74.080 ;
    END
  END sstream_i[12]
  PIN sstream_i[13]
    DIRECTION INPUT ;
    USE SIGNAL ;
    ANTENNAGATEAREA 0.126000 ;
    ANTENNADIFFAREA 2.608200 ;
    PORT
      LAYER met3 ;
        RECT 0.000 76.200 4.000 76.800 ;
    END
  END sstream_i[13]
  PIN sstream_i[14]
    DIRECTION INPUT ;
    USE SIGNAL ;
    ANTENNAGATEAREA 0.126000 ;
    ANTENNADIFFAREA 2.173500 ;
    PORT
      LAYER met3 ;
        RECT 0.000 78.920 4.000 79.520 ;
    END
  END sstream_i[14]
  PIN sstream_i[15]
    DIRECTION INPUT ;
    USE SIGNAL ;
    ANTENNAGATEAREA 0.126000 ;
    ANTENNADIFFAREA 3.042900 ;
    PORT
      LAYER met3 ;
        RECT 0.000 81.640 4.000 82.240 ;
    END
  END sstream_i[15]
  PIN sstream_i[16]
    DIRECTION INPUT ;
    USE SIGNAL ;
    ANTENNAGATEAREA 0.126000 ;
    ANTENNADIFFAREA 2.173500 ;
    PORT
      LAYER met3 ;
        RECT 0.000 84.360 4.000 84.960 ;
    END
  END sstream_i[16]
  PIN sstream_i[17]
    DIRECTION INPUT ;
    USE SIGNAL ;
    ANTENNAGATEAREA 0.126000 ;
    ANTENNADIFFAREA 2.608200 ;
    PORT
      LAYER met3 ;
        RECT 0.000 87.080 4.000 87.680 ;
    END
  END sstream_i[17]
  PIN sstream_i[18]
    DIRECTION INPUT ;
    USE SIGNAL ;
    ANTENNAGATEAREA 0.126000 ;
    ANTENNADIFFAREA 0.434700 ;
    PORT
      LAYER met3 ;
        RECT 0.000 89.800 4.000 90.400 ;
    END
  END sstream_i[18]
  PIN sstream_i[19]
    DIRECTION INPUT ;
    USE SIGNAL ;
    ANTENNAGATEAREA 0.126000 ;
    ANTENNADIFFAREA 2.173500 ;
    PORT
      LAYER met3 ;
        RECT 0.000 92.520 4.000 93.120 ;
    END
  END sstream_i[19]
  PIN sstream_i[1]
    DIRECTION INPUT ;
    USE SIGNAL ;
    ANTENNAGATEAREA 0.126000 ;
    ANTENNADIFFAREA 0.434700 ;
    PORT
      LAYER met3 ;
        RECT 0.000 43.560 4.000 44.160 ;
    END
  END sstream_i[1]
  PIN sstream_i[20]
    DIRECTION INPUT ;
    USE SIGNAL ;
    ANTENNAGATEAREA 0.126000 ;
    ANTENNADIFFAREA 0.434700 ;
    PORT
      LAYER met3 ;
        RECT 0.000 95.240 4.000 95.840 ;
    END
  END sstream_i[20]
  PIN sstream_i[21]
    DIRECTION INPUT ;
    USE SIGNAL ;
    ANTENNAGATEAREA 0.126000 ;
    ANTENNADIFFAREA 1.304100 ;
    PORT
      LAYER met3 ;
        RECT 0.000 97.960 4.000 98.560 ;
    END
  END sstream_i[21]
  PIN sstream_i[22]
    DIRECTION INPUT ;
    USE SIGNAL ;
    ANTENNAGATEAREA 0.126000 ;
    ANTENNADIFFAREA 1.304100 ;
    PORT
      LAYER met3 ;
        RECT 0.000 100.680 4.000 101.280 ;
    END
  END sstream_i[22]
  PIN sstream_i[23]
    DIRECTION INPUT ;
    USE SIGNAL ;
    ANTENNAGATEAREA 0.126000 ;
    ANTENNADIFFAREA 2.173500 ;
    PORT
      LAYER met3 ;
        RECT 0.000 103.400 4.000 104.000 ;
    END
  END sstream_i[23]
  PIN sstream_i[24]
    DIRECTION INPUT ;
    USE SIGNAL ;
    ANTENNAGATEAREA 0.126000 ;
    PORT
      LAYER met3 ;
        RECT 0.000 106.120 4.000 106.720 ;
    END
  END sstream_i[24]
  PIN sstream_i[25]
    DIRECTION INPUT ;
    USE SIGNAL ;
    ANTENNAGATEAREA 0.126000 ;
    ANTENNADIFFAREA 0.869400 ;
    PORT
      LAYER met3 ;
        RECT 0.000 108.840 4.000 109.440 ;
    END
  END sstream_i[25]
  PIN sstream_i[26]
    DIRECTION INPUT ;
    USE SIGNAL ;
    ANTENNAGATEAREA 0.126000 ;
    ANTENNADIFFAREA 0.434700 ;
    PORT
      LAYER met3 ;
        RECT 0.000 111.560 4.000 112.160 ;
    END
  END sstream_i[26]
  PIN sstream_i[27]
    DIRECTION INPUT ;
    USE SIGNAL ;
    ANTENNAGATEAREA 0.126000 ;
    ANTENNADIFFAREA 0.434700 ;
    PORT
      LAYER met3 ;
        RECT 0.000 114.280 4.000 114.880 ;
    END
  END sstream_i[27]
  PIN sstream_i[28]
    DIRECTION INPUT ;
    USE SIGNAL ;
    ANTENNAGATEAREA 0.126000 ;
    ANTENNADIFFAREA 1.304100 ;
    PORT
      LAYER met3 ;
        RECT 0.000 117.000 4.000 117.600 ;
    END
  END sstream_i[28]
  PIN sstream_i[29]
    DIRECTION INPUT ;
    USE SIGNAL ;
    ANTENNAGATEAREA 0.126000 ;
    ANTENNADIFFAREA 0.434700 ;
    PORT
      LAYER met3 ;
        RECT 0.000 119.720 4.000 120.320 ;
    END
  END sstream_i[29]
  PIN sstream_i[2]
    DIRECTION INPUT ;
    USE SIGNAL ;
    ANTENNAGATEAREA 0.126000 ;
    ANTENNADIFFAREA 2.173500 ;
    PORT
      LAYER met3 ;
        RECT 0.000 46.280 4.000 46.880 ;
    END
  END sstream_i[2]
  PIN sstream_i[30]
    DIRECTION INPUT ;
    USE SIGNAL ;
    ANTENNAGATEAREA 0.126000 ;
    ANTENNADIFFAREA 0.434700 ;
    PORT
      LAYER met3 ;
        RECT 0.000 122.440 4.000 123.040 ;
    END
  END sstream_i[30]
  PIN sstream_i[31]
    DIRECTION INPUT ;
    USE SIGNAL ;
    ANTENNAGATEAREA 0.126000 ;
    ANTENNADIFFAREA 2.173500 ;
    PORT
      LAYER met3 ;
        RECT 0.000 125.160 4.000 125.760 ;
    END
  END sstream_i[31]
  PIN sstream_i[32]
    DIRECTION INPUT ;
    USE SIGNAL ;
    ANTENNAGATEAREA 0.126000 ;
    PORT
      LAYER met3 ;
        RECT 0.000 127.880 4.000 128.480 ;
    END
  END sstream_i[32]
  PIN sstream_i[33]
    DIRECTION INPUT ;
    USE SIGNAL ;
    ANTENNAGATEAREA 0.126000 ;
    PORT
      LAYER met3 ;
        RECT 0.000 130.600 4.000 131.200 ;
    END
  END sstream_i[33]
  PIN sstream_i[34]
    DIRECTION INPUT ;
    USE SIGNAL ;
    ANTENNAGATEAREA 0.126000 ;
    PORT
      LAYER met3 ;
        RECT 0.000 133.320 4.000 133.920 ;
    END
  END sstream_i[34]
  PIN sstream_i[35]
    DIRECTION INPUT ;
    USE SIGNAL ;
    ANTENNAGATEAREA 0.126000 ;
    PORT
      LAYER met3 ;
        RECT 0.000 136.040 4.000 136.640 ;
    END
  END sstream_i[35]
  PIN sstream_i[36]
    DIRECTION INPUT ;
    USE SIGNAL ;
    ANTENNAGATEAREA 0.126000 ;
    PORT
      LAYER met3 ;
        RECT 0.000 138.760 4.000 139.360 ;
    END
  END sstream_i[36]
  PIN sstream_i[37]
    DIRECTION INPUT ;
    USE SIGNAL ;
    ANTENNAGATEAREA 0.126000 ;
    PORT
      LAYER met3 ;
        RECT 0.000 141.480 4.000 142.080 ;
    END
  END sstream_i[37]
  PIN sstream_i[38]
    DIRECTION INPUT ;
    USE SIGNAL ;
    ANTENNAGATEAREA 0.126000 ;
    PORT
      LAYER met3 ;
        RECT 0.000 144.200 4.000 144.800 ;
    END
  END sstream_i[38]
  PIN sstream_i[39]
    DIRECTION INPUT ;
    USE SIGNAL ;
    ANTENNAGATEAREA 0.126000 ;
    PORT
      LAYER met3 ;
        RECT 0.000 146.920 4.000 147.520 ;
    END
  END sstream_i[39]
  PIN sstream_i[3]
    DIRECTION INPUT ;
    USE SIGNAL ;
    ANTENNAGATEAREA 0.126000 ;
    ANTENNADIFFAREA 3.042900 ;
    PORT
      LAYER met3 ;
        RECT 0.000 49.000 4.000 49.600 ;
    END
  END sstream_i[3]
  PIN sstream_i[40]
    DIRECTION INPUT ;
    USE SIGNAL ;
    ANTENNAGATEAREA 0.126000 ;
    PORT
      LAYER met3 ;
        RECT 0.000 149.640 4.000 150.240 ;
    END
  END sstream_i[40]
  PIN sstream_i[41]
    DIRECTION INPUT ;
    USE SIGNAL ;
    ANTENNAGATEAREA 0.126000 ;
    PORT
      LAYER met3 ;
        RECT 0.000 152.360 4.000 152.960 ;
    END
  END sstream_i[41]
  PIN sstream_i[42]
    DIRECTION INPUT ;
    USE SIGNAL ;
    ANTENNAGATEAREA 0.126000 ;
    PORT
      LAYER met3 ;
        RECT 0.000 155.080 4.000 155.680 ;
    END
  END sstream_i[42]
  PIN sstream_i[43]
    DIRECTION INPUT ;
    USE SIGNAL ;
    ANTENNAGATEAREA 0.126000 ;
    PORT
      LAYER met3 ;
        RECT 0.000 157.800 4.000 158.400 ;
    END
  END sstream_i[43]
  PIN sstream_i[44]
    DIRECTION INPUT ;
    USE SIGNAL ;
    ANTENNAGATEAREA 0.126000 ;
    PORT
      LAYER met3 ;
        RECT 0.000 160.520 4.000 161.120 ;
    END
  END sstream_i[44]
  PIN sstream_i[45]
    DIRECTION INPUT ;
    USE SIGNAL ;
    ANTENNAGATEAREA 0.126000 ;
    PORT
      LAYER met3 ;
        RECT 0.000 163.240 4.000 163.840 ;
    END
  END sstream_i[45]
  PIN sstream_i[46]
    DIRECTION INPUT ;
    USE SIGNAL ;
    ANTENNAGATEAREA 0.126000 ;
    PORT
      LAYER met3 ;
        RECT 0.000 165.960 4.000 166.560 ;
    END
  END sstream_i[46]
  PIN sstream_i[47]
    DIRECTION INPUT ;
    USE SIGNAL ;
    ANTENNAGATEAREA 0.126000 ;
    PORT
      LAYER met3 ;
        RECT 0.000 168.680 4.000 169.280 ;
    END
  END sstream_i[47]
  PIN sstream_i[48]
    DIRECTION INPUT ;
    USE SIGNAL ;
    ANTENNAGATEAREA 0.126000 ;
    PORT
      LAYER met3 ;
        RECT 0.000 171.400 4.000 172.000 ;
    END
  END sstream_i[48]
  PIN sstream_i[49]
    DIRECTION INPUT ;
    USE SIGNAL ;
    ANTENNAGATEAREA 0.126000 ;
    PORT
      LAYER met3 ;
        RECT 0.000 174.120 4.000 174.720 ;
    END
  END sstream_i[49]
  PIN sstream_i[4]
    DIRECTION INPUT ;
    USE SIGNAL ;
    ANTENNAGATEAREA 0.126000 ;
    ANTENNADIFFAREA 0.434700 ;
    PORT
      LAYER met3 ;
        RECT 0.000 51.720 4.000 52.320 ;
    END
  END sstream_i[4]
  PIN sstream_i[50]
    DIRECTION INPUT ;
    USE SIGNAL ;
    ANTENNAGATEAREA 0.126000 ;
    PORT
      LAYER met3 ;
        RECT 0.000 176.840 4.000 177.440 ;
    END
  END sstream_i[50]
  PIN sstream_i[51]
    DIRECTION INPUT ;
    USE SIGNAL ;
    ANTENNAGATEAREA 0.126000 ;
    PORT
      LAYER met3 ;
        RECT 0.000 179.560 4.000 180.160 ;
    END
  END sstream_i[51]
  PIN sstream_i[52]
    DIRECTION INPUT ;
    USE SIGNAL ;
    ANTENNAGATEAREA 0.126000 ;
    PORT
      LAYER met3 ;
        RECT 0.000 182.280 4.000 182.880 ;
    END
  END sstream_i[52]
  PIN sstream_i[53]
    DIRECTION INPUT ;
    USE SIGNAL ;
    ANTENNAGATEAREA 0.126000 ;
    PORT
      LAYER met3 ;
        RECT 0.000 185.000 4.000 185.600 ;
    END
  END sstream_i[53]
  PIN sstream_i[54]
    DIRECTION INPUT ;
    USE SIGNAL ;
    ANTENNAGATEAREA 0.126000 ;
    PORT
      LAYER met3 ;
        RECT 0.000 187.720 4.000 188.320 ;
    END
  END sstream_i[54]
  PIN sstream_i[55]
    DIRECTION INPUT ;
    USE SIGNAL ;
    ANTENNAGATEAREA 0.126000 ;
    PORT
      LAYER met3 ;
        RECT 0.000 190.440 4.000 191.040 ;
    END
  END sstream_i[55]
  PIN sstream_i[56]
    DIRECTION INPUT ;
    USE SIGNAL ;
    ANTENNAGATEAREA 0.126000 ;
    PORT
      LAYER met3 ;
        RECT 0.000 193.160 4.000 193.760 ;
    END
  END sstream_i[56]
  PIN sstream_i[57]
    DIRECTION INPUT ;
    USE SIGNAL ;
    ANTENNAGATEAREA 0.126000 ;
    PORT
      LAYER met3 ;
        RECT 0.000 195.880 4.000 196.480 ;
    END
  END sstream_i[57]
  PIN sstream_i[58]
    DIRECTION INPUT ;
    USE SIGNAL ;
    ANTENNAGATEAREA 0.126000 ;
    PORT
      LAYER met3 ;
        RECT 0.000 198.600 4.000 199.200 ;
    END
  END sstream_i[58]
  PIN sstream_i[59]
    DIRECTION INPUT ;
    USE SIGNAL ;
    ANTENNAGATEAREA 0.126000 ;
    PORT
      LAYER met3 ;
        RECT 0.000 201.320 4.000 201.920 ;
    END
  END sstream_i[59]
  PIN sstream_i[5]
    DIRECTION INPUT ;
    USE SIGNAL ;
    ANTENNAGATEAREA 0.126000 ;
    ANTENNADIFFAREA 3.477600 ;
    PORT
      LAYER met3 ;
        RECT 0.000 54.440 4.000 55.040 ;
    END
  END sstream_i[5]
  PIN sstream_i[60]
    DIRECTION INPUT ;
    USE SIGNAL ;
    ANTENNAGATEAREA 0.126000 ;
    PORT
      LAYER met3 ;
        RECT 0.000 204.040 4.000 204.640 ;
    END
  END sstream_i[60]
  PIN sstream_i[61]
    DIRECTION INPUT ;
    USE SIGNAL ;
    ANTENNAGATEAREA 0.126000 ;
    PORT
      LAYER met3 ;
        RECT 0.000 206.760 4.000 207.360 ;
    END
  END sstream_i[61]
  PIN sstream_i[62]
    DIRECTION INPUT ;
    USE SIGNAL ;
    ANTENNAGATEAREA 0.126000 ;
    PORT
      LAYER met3 ;
        RECT 0.000 209.480 4.000 210.080 ;
    END
  END sstream_i[62]
  PIN sstream_i[63]
    DIRECTION INPUT ;
    USE SIGNAL ;
    ANTENNAGATEAREA 0.126000 ;
    PORT
      LAYER met3 ;
        RECT 0.000 212.200 4.000 212.800 ;
    END
  END sstream_i[63]
  PIN sstream_i[64]
    DIRECTION INPUT ;
    USE SIGNAL ;
    ANTENNAGATEAREA 0.126000 ;
    PORT
      LAYER met3 ;
        RECT 0.000 214.920 4.000 215.520 ;
    END
  END sstream_i[64]
  PIN sstream_i[65]
    DIRECTION INPUT ;
    USE SIGNAL ;
    ANTENNAGATEAREA 0.126000 ;
    PORT
      LAYER met3 ;
        RECT 0.000 217.640 4.000 218.240 ;
    END
  END sstream_i[65]
  PIN sstream_i[66]
    DIRECTION INPUT ;
    USE SIGNAL ;
    ANTENNAGATEAREA 0.126000 ;
    PORT
      LAYER met3 ;
        RECT 0.000 220.360 4.000 220.960 ;
    END
  END sstream_i[66]
  PIN sstream_i[67]
    DIRECTION INPUT ;
    USE SIGNAL ;
    ANTENNAGATEAREA 0.126000 ;
    PORT
      LAYER met3 ;
        RECT 0.000 223.080 4.000 223.680 ;
    END
  END sstream_i[67]
  PIN sstream_i[68]
    DIRECTION INPUT ;
    USE SIGNAL ;
    ANTENNAGATEAREA 0.126000 ;
    PORT
      LAYER met3 ;
        RECT 0.000 225.800 4.000 226.400 ;
    END
  END sstream_i[68]
  PIN sstream_i[69]
    DIRECTION INPUT ;
    USE SIGNAL ;
    ANTENNAGATEAREA 0.126000 ;
    PORT
      LAYER met3 ;
        RECT 0.000 228.520 4.000 229.120 ;
    END
  END sstream_i[69]
  PIN sstream_i[6]
    DIRECTION INPUT ;
    USE SIGNAL ;
    ANTENNAGATEAREA 0.126000 ;
    ANTENNADIFFAREA 0.434700 ;
    PORT
      LAYER met3 ;
        RECT 0.000 57.160 4.000 57.760 ;
    END
  END sstream_i[6]
  PIN sstream_i[70]
    DIRECTION INPUT ;
    USE SIGNAL ;
    ANTENNAGATEAREA 0.126000 ;
    PORT
      LAYER met3 ;
        RECT 0.000 231.240 4.000 231.840 ;
    END
  END sstream_i[70]
  PIN sstream_i[71]
    DIRECTION INPUT ;
    USE SIGNAL ;
    ANTENNAGATEAREA 0.126000 ;
    PORT
      LAYER met3 ;
        RECT 0.000 233.960 4.000 234.560 ;
    END
  END sstream_i[71]
  PIN sstream_i[72]
    DIRECTION INPUT ;
    USE SIGNAL ;
    ANTENNAGATEAREA 0.126000 ;
    PORT
      LAYER met3 ;
        RECT 0.000 236.680 4.000 237.280 ;
    END
  END sstream_i[72]
  PIN sstream_i[73]
    DIRECTION INPUT ;
    USE SIGNAL ;
    ANTENNAGATEAREA 0.126000 ;
    PORT
      LAYER met3 ;
        RECT 0.000 239.400 4.000 240.000 ;
    END
  END sstream_i[73]
  PIN sstream_i[74]
    DIRECTION INPUT ;
    USE SIGNAL ;
    ANTENNAGATEAREA 0.126000 ;
    PORT
      LAYER met3 ;
        RECT 0.000 242.120 4.000 242.720 ;
    END
  END sstream_i[74]
  PIN sstream_i[75]
    DIRECTION INPUT ;
    USE SIGNAL ;
    ANTENNAGATEAREA 0.126000 ;
    PORT
      LAYER met3 ;
        RECT 0.000 244.840 4.000 245.440 ;
    END
  END sstream_i[75]
  PIN sstream_i[76]
    DIRECTION INPUT ;
    USE SIGNAL ;
    ANTENNAGATEAREA 0.126000 ;
    PORT
      LAYER met3 ;
        RECT 0.000 247.560 4.000 248.160 ;
    END
  END sstream_i[76]
  PIN sstream_i[77]
    DIRECTION INPUT ;
    USE SIGNAL ;
    ANTENNAGATEAREA 0.126000 ;
    PORT
      LAYER met3 ;
        RECT 0.000 250.280 4.000 250.880 ;
    END
  END sstream_i[77]
  PIN sstream_i[78]
    DIRECTION INPUT ;
    USE SIGNAL ;
    ANTENNAGATEAREA 0.126000 ;
    PORT
      LAYER met3 ;
        RECT 0.000 253.000 4.000 253.600 ;
    END
  END sstream_i[78]
  PIN sstream_i[79]
    DIRECTION INPUT ;
    USE SIGNAL ;
    ANTENNAGATEAREA 0.126000 ;
    PORT
      LAYER met3 ;
        RECT 0.000 255.720 4.000 256.320 ;
    END
  END sstream_i[79]
  PIN sstream_i[7]
    DIRECTION INPUT ;
    USE SIGNAL ;
    ANTENNAGATEAREA 0.126000 ;
    ANTENNADIFFAREA 2.173500 ;
    PORT
      LAYER met3 ;
        RECT 0.000 59.880 4.000 60.480 ;
    END
  END sstream_i[7]
  PIN sstream_i[80]
    DIRECTION INPUT ;
    USE SIGNAL ;
    ANTENNAGATEAREA 0.126000 ;
    PORT
      LAYER met3 ;
        RECT 0.000 258.440 4.000 259.040 ;
    END
  END sstream_i[80]
  PIN sstream_i[81]
    DIRECTION INPUT ;
    USE SIGNAL ;
    ANTENNAGATEAREA 0.126000 ;
    PORT
      LAYER met3 ;
        RECT 0.000 261.160 4.000 261.760 ;
    END
  END sstream_i[81]
  PIN sstream_i[82]
    DIRECTION INPUT ;
    USE SIGNAL ;
    ANTENNAGATEAREA 0.126000 ;
    PORT
      LAYER met3 ;
        RECT 0.000 263.880 4.000 264.480 ;
    END
  END sstream_i[82]
  PIN sstream_i[83]
    DIRECTION INPUT ;
    USE SIGNAL ;
    ANTENNAGATEAREA 0.126000 ;
    PORT
      LAYER met3 ;
        RECT 0.000 266.600 4.000 267.200 ;
    END
  END sstream_i[83]
  PIN sstream_i[84]
    DIRECTION INPUT ;
    USE SIGNAL ;
    ANTENNAGATEAREA 0.126000 ;
    PORT
      LAYER met3 ;
        RECT 0.000 269.320 4.000 269.920 ;
    END
  END sstream_i[84]
  PIN sstream_i[85]
    DIRECTION INPUT ;
    USE SIGNAL ;
    ANTENNAGATEAREA 0.126000 ;
    PORT
      LAYER met3 ;
        RECT 0.000 272.040 4.000 272.640 ;
    END
  END sstream_i[85]
  PIN sstream_i[86]
    DIRECTION INPUT ;
    USE SIGNAL ;
    ANTENNAGATEAREA 0.126000 ;
    PORT
      LAYER met3 ;
        RECT 0.000 274.760 4.000 275.360 ;
    END
  END sstream_i[86]
  PIN sstream_i[87]
    DIRECTION INPUT ;
    USE SIGNAL ;
    ANTENNAGATEAREA 0.126000 ;
    PORT
      LAYER met3 ;
        RECT 0.000 277.480 4.000 278.080 ;
    END
  END sstream_i[87]
  PIN sstream_i[88]
    DIRECTION INPUT ;
    USE SIGNAL ;
    ANTENNAGATEAREA 0.126000 ;
    PORT
      LAYER met3 ;
        RECT 0.000 280.200 4.000 280.800 ;
    END
  END sstream_i[88]
  PIN sstream_i[89]
    DIRECTION INPUT ;
    USE SIGNAL ;
    ANTENNAGATEAREA 0.126000 ;
    PORT
      LAYER met3 ;
        RECT 0.000 282.920 4.000 283.520 ;
    END
  END sstream_i[89]
  PIN sstream_i[8]
    DIRECTION INPUT ;
    USE SIGNAL ;
    ANTENNAGATEAREA 0.126000 ;
    ANTENNADIFFAREA 0.869400 ;
    PORT
      LAYER met3 ;
        RECT 0.000 62.600 4.000 63.200 ;
    END
  END sstream_i[8]
  PIN sstream_i[90]
    DIRECTION INPUT ;
    USE SIGNAL ;
    ANTENNAGATEAREA 0.126000 ;
    PORT
      LAYER met3 ;
        RECT 0.000 285.640 4.000 286.240 ;
    END
  END sstream_i[90]
  PIN sstream_i[91]
    DIRECTION INPUT ;
    USE SIGNAL ;
    ANTENNAGATEAREA 0.126000 ;
    PORT
      LAYER met3 ;
        RECT 0.000 288.360 4.000 288.960 ;
    END
  END sstream_i[91]
  PIN sstream_i[92]
    DIRECTION INPUT ;
    USE SIGNAL ;
    ANTENNAGATEAREA 0.126000 ;
    PORT
      LAYER met3 ;
        RECT 0.000 291.080 4.000 291.680 ;
    END
  END sstream_i[92]
  PIN sstream_i[93]
    DIRECTION INPUT ;
    USE SIGNAL ;
    ANTENNAGATEAREA 0.126000 ;
    PORT
      LAYER met3 ;
        RECT 0.000 293.800 4.000 294.400 ;
    END
  END sstream_i[93]
  PIN sstream_i[94]
    DIRECTION INPUT ;
    USE SIGNAL ;
    ANTENNAGATEAREA 0.126000 ;
    PORT
      LAYER met3 ;
        RECT 0.000 296.520 4.000 297.120 ;
    END
  END sstream_i[94]
  PIN sstream_i[95]
    DIRECTION INPUT ;
    USE SIGNAL ;
    ANTENNAGATEAREA 0.126000 ;
    PORT
      LAYER met3 ;
        RECT 0.000 299.240 4.000 299.840 ;
    END
  END sstream_i[95]
  PIN sstream_i[96]
    DIRECTION INPUT ;
    USE SIGNAL ;
    ANTENNAGATEAREA 0.126000 ;
    PORT
      LAYER met3 ;
        RECT 0.000 301.960 4.000 302.560 ;
    END
  END sstream_i[96]
  PIN sstream_i[97]
    DIRECTION INPUT ;
    USE SIGNAL ;
    ANTENNAGATEAREA 0.126000 ;
    PORT
      LAYER met3 ;
        RECT 0.000 304.680 4.000 305.280 ;
    END
  END sstream_i[97]
  PIN sstream_i[98]
    DIRECTION INPUT ;
    USE SIGNAL ;
    ANTENNAGATEAREA 0.126000 ;
    PORT
      LAYER met3 ;
        RECT 0.000 307.400 4.000 308.000 ;
    END
  END sstream_i[98]
  PIN sstream_i[99]
    DIRECTION INPUT ;
    USE SIGNAL ;
    ANTENNAGATEAREA 0.126000 ;
    PORT
      LAYER met3 ;
        RECT 0.000 310.120 4.000 310.720 ;
    END
  END sstream_i[99]
  PIN sstream_i[9]
    DIRECTION INPUT ;
    USE SIGNAL ;
    ANTENNAGATEAREA 0.126000 ;
    ANTENNADIFFAREA 3.042900 ;
    PORT
      LAYER met3 ;
        RECT 0.000 65.320 4.000 65.920 ;
    END
  END sstream_i[9]
  PIN sstream_o
    DIRECTION OUTPUT TRISTATE ;
    USE SIGNAL ;
    ANTENNAGATEAREA 2.232000 ;
    ANTENNADIFFAREA 0.934000 ;
    PORT
      LAYER met3 ;
        RECT 0.000 356.360 4.000 356.960 ;
    END
  END sstream_o
  PIN tex_addr_i[0]
    DIRECTION INPUT ;
    USE SIGNAL ;
    ANTENNAGATEAREA 0.990000 ;
    PORT
      LAYER met2 ;
        RECT 21.250 0.000 21.530 4.000 ;
    END
  END tex_addr_i[0]
  PIN tex_addr_i[10]
    DIRECTION INPUT ;
    USE SIGNAL ;
    ANTENNAGATEAREA 0.373500 ;
    ANTENNADIFFAREA 0.869400 ;
    PORT
      LAYER met2 ;
        RECT 48.850 0.000 49.130 4.000 ;
    END
  END tex_addr_i[10]
  PIN tex_addr_i[11]
    DIRECTION INPUT ;
    USE SIGNAL ;
    ANTENNAGATEAREA 0.373500 ;
    ANTENNADIFFAREA 0.869400 ;
    PORT
      LAYER met2 ;
        RECT 51.610 0.000 51.890 4.000 ;
    END
  END tex_addr_i[11]
  PIN tex_addr_i[12]
    DIRECTION INPUT ;
    USE SIGNAL ;
    ANTENNAGATEAREA 0.373500 ;
    ANTENNADIFFAREA 0.869400 ;
    PORT
      LAYER met2 ;
        RECT 54.370 0.000 54.650 4.000 ;
    END
  END tex_addr_i[12]
  PIN tex_addr_i[13]
    DIRECTION INPUT ;
    USE SIGNAL ;
    ANTENNAGATEAREA 0.252000 ;
    ANTENNADIFFAREA 0.869400 ;
    PORT
      LAYER met2 ;
        RECT 57.130 0.000 57.410 4.000 ;
    END
  END tex_addr_i[13]
  PIN tex_addr_i[14]
    DIRECTION INPUT ;
    USE SIGNAL ;
    ANTENNAGATEAREA 0.373500 ;
    ANTENNADIFFAREA 0.869400 ;
    PORT
      LAYER met2 ;
        RECT 59.890 0.000 60.170 4.000 ;
    END
  END tex_addr_i[14]
  PIN tex_addr_i[15]
    DIRECTION INPUT ;
    USE SIGNAL ;
    ANTENNAGATEAREA 0.495000 ;
    ANTENNADIFFAREA 0.869400 ;
    PORT
      LAYER met2 ;
        RECT 62.650 0.000 62.930 4.000 ;
    END
  END tex_addr_i[15]
  PIN tex_addr_i[16]
    DIRECTION INPUT ;
    USE SIGNAL ;
    ANTENNAGATEAREA 1.363500 ;
    PORT
      LAYER met2 ;
        RECT 65.410 0.000 65.690 4.000 ;
    END
  END tex_addr_i[16]
  PIN tex_addr_i[17]
    DIRECTION INPUT ;
    USE SIGNAL ;
    ANTENNAGATEAREA 1.237500 ;
    ANTENNADIFFAREA 0.434700 ;
    PORT
      LAYER met2 ;
        RECT 68.170 0.000 68.450 4.000 ;
    END
  END tex_addr_i[17]
  PIN tex_addr_i[18]
    DIRECTION INPUT ;
    USE SIGNAL ;
    ANTENNAGATEAREA 1.237500 ;
    PORT
      LAYER met2 ;
        RECT 70.930 0.000 71.210 4.000 ;
    END
  END tex_addr_i[18]
  PIN tex_addr_i[19]
    DIRECTION INPUT ;
    USE SIGNAL ;
    ANTENNAGATEAREA 0.990000 ;
    PORT
      LAYER met2 ;
        RECT 73.690 0.000 73.970 4.000 ;
    END
  END tex_addr_i[19]
  PIN tex_addr_i[1]
    DIRECTION INPUT ;
    USE SIGNAL ;
    ANTENNAGATEAREA 0.495000 ;
    ANTENNADIFFAREA 0.434700 ;
    PORT
      LAYER met2 ;
        RECT 24.010 0.000 24.290 4.000 ;
    END
  END tex_addr_i[1]
  PIN tex_addr_i[20]
    DIRECTION INPUT ;
    USE SIGNAL ;
    ANTENNAGATEAREA 1.116000 ;
    PORT
      LAYER met2 ;
        RECT 76.450 0.000 76.730 4.000 ;
    END
  END tex_addr_i[20]
  PIN tex_addr_i[21]
    DIRECTION INPUT ;
    USE SIGNAL ;
    ANTENNAGATEAREA 0.990000 ;
    PORT
      LAYER met2 ;
        RECT 79.210 0.000 79.490 4.000 ;
    END
  END tex_addr_i[21]
  PIN tex_addr_i[22]
    DIRECTION INPUT ;
    USE SIGNAL ;
    ANTENNAGATEAREA 1.237500 ;
    PORT
      LAYER met2 ;
        RECT 81.970 0.000 82.250 4.000 ;
    END
  END tex_addr_i[22]
  PIN tex_addr_i[23]
    DIRECTION INPUT ;
    USE SIGNAL ;
    ANTENNAGATEAREA 0.990000 ;
    PORT
      LAYER met2 ;
        RECT 84.730 0.000 85.010 4.000 ;
    END
  END tex_addr_i[23]
  PIN tex_addr_i[24]
    DIRECTION INPUT ;
    USE SIGNAL ;
    ANTENNAGATEAREA 1.237500 ;
    PORT
      LAYER met2 ;
        RECT 87.490 0.000 87.770 4.000 ;
    END
  END tex_addr_i[24]
  PIN tex_addr_i[25]
    DIRECTION INPUT ;
    USE SIGNAL ;
    ANTENNAGATEAREA 0.868500 ;
    PORT
      LAYER met2 ;
        RECT 90.250 0.000 90.530 4.000 ;
    END
  END tex_addr_i[25]
  PIN tex_addr_i[26]
    DIRECTION INPUT ;
    USE SIGNAL ;
    ANTENNAGATEAREA 0.621000 ;
    PORT
      LAYER met2 ;
        RECT 93.010 0.000 93.290 4.000 ;
    END
  END tex_addr_i[26]
  PIN tex_addr_i[27]
    DIRECTION INPUT ;
    USE SIGNAL ;
    ANTENNAGATEAREA 0.742500 ;
    PORT
      LAYER met2 ;
        RECT 95.770 0.000 96.050 4.000 ;
    END
  END tex_addr_i[27]
  PIN tex_addr_i[28]
    DIRECTION INPUT ;
    USE SIGNAL ;
    ANTENNAGATEAREA 0.373500 ;
    PORT
      LAYER met2 ;
        RECT 98.530 0.000 98.810 4.000 ;
    END
  END tex_addr_i[28]
  PIN tex_addr_i[29]
    DIRECTION INPUT ;
    USE SIGNAL ;
    ANTENNAGATEAREA 0.373500 ;
    PORT
      LAYER met2 ;
        RECT 101.290 0.000 101.570 4.000 ;
    END
  END tex_addr_i[29]
  PIN tex_addr_i[2]
    DIRECTION INPUT ;
    USE SIGNAL ;
    ANTENNAGATEAREA 0.742500 ;
    PORT
      LAYER met2 ;
        RECT 26.770 0.000 27.050 4.000 ;
    END
  END tex_addr_i[2]
  PIN tex_addr_i[30]
    DIRECTION INPUT ;
    USE SIGNAL ;
    ANTENNAGATEAREA 0.373500 ;
    PORT
      LAYER met2 ;
        RECT 104.050 0.000 104.330 4.000 ;
    END
  END tex_addr_i[30]
  PIN tex_addr_i[31]
    DIRECTION INPUT ;
    USE SIGNAL ;
    ANTENNAGATEAREA 0.495000 ;
    PORT
      LAYER met2 ;
        RECT 106.810 0.000 107.090 4.000 ;
    END
  END tex_addr_i[31]
  PIN tex_addr_i[3]
    DIRECTION INPUT ;
    USE SIGNAL ;
    ANTENNAGATEAREA 0.373500 ;
    ANTENNADIFFAREA 0.869400 ;
    PORT
      LAYER met2 ;
        RECT 29.530 0.000 29.810 4.000 ;
    END
  END tex_addr_i[3]
  PIN tex_addr_i[4]
    DIRECTION INPUT ;
    USE SIGNAL ;
    ANTENNAGATEAREA 0.373500 ;
    PORT
      LAYER met2 ;
        RECT 32.290 0.000 32.570 4.000 ;
    END
  END tex_addr_i[4]
  PIN tex_addr_i[5]
    DIRECTION INPUT ;
    USE SIGNAL ;
    ANTENNAGATEAREA 0.252000 ;
    ANTENNADIFFAREA 0.869400 ;
    PORT
      LAYER met2 ;
        RECT 35.050 0.000 35.330 4.000 ;
    END
  END tex_addr_i[5]
  PIN tex_addr_i[6]
    DIRECTION INPUT ;
    USE SIGNAL ;
    ANTENNAGATEAREA 1.980000 ;
    PORT
      LAYER met2 ;
        RECT 37.810 0.000 38.090 4.000 ;
    END
  END tex_addr_i[6]
  PIN tex_addr_i[7]
    DIRECTION INPUT ;
    USE SIGNAL ;
    ANTENNAGATEAREA 0.495000 ;
    ANTENNADIFFAREA 0.869400 ;
    PORT
      LAYER met2 ;
        RECT 40.570 0.000 40.850 4.000 ;
    END
  END tex_addr_i[7]
  PIN tex_addr_i[8]
    DIRECTION INPUT ;
    USE SIGNAL ;
    ANTENNAGATEAREA 0.621000 ;
    ANTENNADIFFAREA 0.869400 ;
    PORT
      LAYER met2 ;
        RECT 43.330 0.000 43.610 4.000 ;
    END
  END tex_addr_i[8]
  PIN tex_addr_i[9]
    DIRECTION INPUT ;
    USE SIGNAL ;
    ANTENNAGATEAREA 0.990000 ;
    PORT
      LAYER met2 ;
        RECT 46.090 0.000 46.370 4.000 ;
    END
  END tex_addr_i[9]
  PIN tex_fly_o
    DIRECTION OUTPUT TRISTATE ;
    USE SIGNAL ;
    ANTENNAGATEAREA 0.247500 ;
    ANTENNADIFFAREA 0.924000 ;
    PORT
      LAYER met2 ;
        RECT 12.970 0.000 13.250 4.000 ;
    END
  END tex_fly_o
  PIN tex_height_i[0]
    DIRECTION INPUT ;
    USE SIGNAL ;
    ANTENNAGATEAREA 1.363500 ;
    ANTENNADIFFAREA 0.434700 ;
    PORT
      LAYER met2 ;
        RECT 153.730 0.000 154.010 4.000 ;
    END
  END tex_height_i[0]
  PIN tex_height_i[10]
    DIRECTION INPUT ;
    USE SIGNAL ;
    ANTENNAGATEAREA 1.363500 ;
    PORT
      LAYER met2 ;
        RECT 181.330 0.000 181.610 4.000 ;
    END
  END tex_height_i[10]
  PIN tex_height_i[11]
    DIRECTION INPUT ;
    USE SIGNAL ;
    ANTENNAGATEAREA 0.823500 ;
    PORT
      LAYER met2 ;
        RECT 184.090 0.000 184.370 4.000 ;
    END
  END tex_height_i[11]
  PIN tex_height_i[12]
    DIRECTION INPUT ;
    USE SIGNAL ;
    ANTENNAGATEAREA 0.868500 ;
    PORT
      LAYER met2 ;
        RECT 186.850 0.000 187.130 4.000 ;
    END
  END tex_height_i[12]
  PIN tex_height_i[13]
    DIRECTION INPUT ;
    USE SIGNAL ;
    ANTENNAGATEAREA 1.116000 ;
    PORT
      LAYER met2 ;
        RECT 189.610 0.000 189.890 4.000 ;
    END
  END tex_height_i[13]
  PIN tex_height_i[14]
    DIRECTION INPUT ;
    USE SIGNAL ;
    ANTENNAGATEAREA 0.625500 ;
    PORT
      LAYER met2 ;
        RECT 192.370 0.000 192.650 4.000 ;
    END
  END tex_height_i[14]
  PIN tex_height_i[15]
    DIRECTION INPUT ;
    USE SIGNAL ;
    ANTENNAGATEAREA 1.980000 ;
    PORT
      LAYER met2 ;
        RECT 195.130 0.000 195.410 4.000 ;
    END
  END tex_height_i[15]
  PIN tex_height_i[1]
    DIRECTION INPUT ;
    USE SIGNAL ;
    ANTENNAGATEAREA 1.363500 ;
    PORT
      LAYER met2 ;
        RECT 156.490 0.000 156.770 4.000 ;
    END
  END tex_height_i[1]
  PIN tex_height_i[2]
    DIRECTION INPUT ;
    USE SIGNAL ;
    ANTENNAGATEAREA 0.823500 ;
    PORT
      LAYER met2 ;
        RECT 159.250 0.000 159.530 4.000 ;
    END
  END tex_height_i[2]
  PIN tex_height_i[3]
    DIRECTION INPUT ;
    USE SIGNAL ;
    ANTENNAGATEAREA 0.868500 ;
    PORT
      LAYER met2 ;
        RECT 162.010 0.000 162.290 4.000 ;
    END
  END tex_height_i[3]
  PIN tex_height_i[4]
    DIRECTION INPUT ;
    USE SIGNAL ;
    ANTENNAGATEAREA 0.868500 ;
    PORT
      LAYER met2 ;
        RECT 164.770 0.000 165.050 4.000 ;
    END
  END tex_height_i[4]
  PIN tex_height_i[5]
    DIRECTION INPUT ;
    USE SIGNAL ;
    ANTENNAGATEAREA 1.363500 ;
    PORT
      LAYER met2 ;
        RECT 167.530 0.000 167.810 4.000 ;
    END
  END tex_height_i[5]
  PIN tex_height_i[6]
    DIRECTION INPUT ;
    USE SIGNAL ;
    ANTENNAGATEAREA 0.823500 ;
    ANTENNADIFFAREA 0.434700 ;
    PORT
      LAYER met2 ;
        RECT 170.290 0.000 170.570 4.000 ;
    END
  END tex_height_i[6]
  PIN tex_height_i[7]
    DIRECTION INPUT ;
    USE SIGNAL ;
    ANTENNAGATEAREA 1.363500 ;
    PORT
      LAYER met2 ;
        RECT 173.050 0.000 173.330 4.000 ;
    END
  END tex_height_i[7]
  PIN tex_height_i[8]
    DIRECTION INPUT ;
    USE SIGNAL ;
    ANTENNAGATEAREA 0.823500 ;
    PORT
      LAYER met2 ;
        RECT 175.810 0.000 176.090 4.000 ;
    END
  END tex_height_i[8]
  PIN tex_height_i[9]
    DIRECTION INPUT ;
    USE SIGNAL ;
    ANTENNAGATEAREA 0.747000 ;
    PORT
      LAYER met2 ;
        RECT 178.570 0.000 178.850 4.000 ;
    END
  END tex_height_i[9]
  PIN tex_mport_i[0]
    DIRECTION INPUT ;
    USE SIGNAL ;
    ANTENNAGATEAREA 0.126000 ;
    PORT
      LAYER met2 ;
        RECT 30.910 396.000 31.190 400.000 ;
    END
  END tex_mport_i[0]
  PIN tex_mport_i[10]
    DIRECTION INPUT ;
    USE SIGNAL ;
    PORT
      LAYER met2 ;
        RECT 58.510 396.000 58.790 400.000 ;
    END
  END tex_mport_i[10]
  PIN tex_mport_i[11]
    DIRECTION INPUT ;
    USE SIGNAL ;
    PORT
      LAYER met2 ;
        RECT 61.270 396.000 61.550 400.000 ;
    END
  END tex_mport_i[11]
  PIN tex_mport_i[12]
    DIRECTION INPUT ;
    USE SIGNAL ;
    PORT
      LAYER met2 ;
        RECT 64.030 396.000 64.310 400.000 ;
    END
  END tex_mport_i[12]
  PIN tex_mport_i[13]
    DIRECTION INPUT ;
    USE SIGNAL ;
    PORT
      LAYER met2 ;
        RECT 66.790 396.000 67.070 400.000 ;
    END
  END tex_mport_i[13]
  PIN tex_mport_i[14]
    DIRECTION INPUT ;
    USE SIGNAL ;
    PORT
      LAYER met2 ;
        RECT 69.550 396.000 69.830 400.000 ;
    END
  END tex_mport_i[14]
  PIN tex_mport_i[15]
    DIRECTION INPUT ;
    USE SIGNAL ;
    PORT
      LAYER met2 ;
        RECT 72.310 396.000 72.590 400.000 ;
    END
  END tex_mport_i[15]
  PIN tex_mport_i[16]
    DIRECTION INPUT ;
    USE SIGNAL ;
    PORT
      LAYER met2 ;
        RECT 75.070 396.000 75.350 400.000 ;
    END
  END tex_mport_i[16]
  PIN tex_mport_i[17]
    DIRECTION INPUT ;
    USE SIGNAL ;
    PORT
      LAYER met2 ;
        RECT 77.830 396.000 78.110 400.000 ;
    END
  END tex_mport_i[17]
  PIN tex_mport_i[18]
    DIRECTION INPUT ;
    USE SIGNAL ;
    PORT
      LAYER met2 ;
        RECT 80.590 396.000 80.870 400.000 ;
    END
  END tex_mport_i[18]
  PIN tex_mport_i[19]
    DIRECTION INPUT ;
    USE SIGNAL ;
    PORT
      LAYER met2 ;
        RECT 83.350 396.000 83.630 400.000 ;
    END
  END tex_mport_i[19]
  PIN tex_mport_i[1]
    DIRECTION INPUT ;
    USE SIGNAL ;
    ANTENNAGATEAREA 0.126000 ;
    PORT
      LAYER met2 ;
        RECT 33.670 396.000 33.950 400.000 ;
    END
  END tex_mport_i[1]
  PIN tex_mport_i[20]
    DIRECTION INPUT ;
    USE SIGNAL ;
    PORT
      LAYER met2 ;
        RECT 86.110 396.000 86.390 400.000 ;
    END
  END tex_mport_i[20]
  PIN tex_mport_i[21]
    DIRECTION INPUT ;
    USE SIGNAL ;
    PORT
      LAYER met2 ;
        RECT 88.870 396.000 89.150 400.000 ;
    END
  END tex_mport_i[21]
  PIN tex_mport_i[22]
    DIRECTION INPUT ;
    USE SIGNAL ;
    PORT
      LAYER met2 ;
        RECT 91.630 396.000 91.910 400.000 ;
    END
  END tex_mport_i[22]
  PIN tex_mport_i[23]
    DIRECTION INPUT ;
    USE SIGNAL ;
    PORT
      LAYER met2 ;
        RECT 94.390 396.000 94.670 400.000 ;
    END
  END tex_mport_i[23]
  PIN tex_mport_i[24]
    DIRECTION INPUT ;
    USE SIGNAL ;
    PORT
      LAYER met2 ;
        RECT 97.150 396.000 97.430 400.000 ;
    END
  END tex_mport_i[24]
  PIN tex_mport_i[25]
    DIRECTION INPUT ;
    USE SIGNAL ;
    PORT
      LAYER met2 ;
        RECT 99.910 396.000 100.190 400.000 ;
    END
  END tex_mport_i[25]
  PIN tex_mport_i[26]
    DIRECTION INPUT ;
    USE SIGNAL ;
    PORT
      LAYER met2 ;
        RECT 102.670 396.000 102.950 400.000 ;
    END
  END tex_mport_i[26]
  PIN tex_mport_i[27]
    DIRECTION INPUT ;
    USE SIGNAL ;
    PORT
      LAYER met2 ;
        RECT 105.430 396.000 105.710 400.000 ;
    END
  END tex_mport_i[27]
  PIN tex_mport_i[28]
    DIRECTION INPUT ;
    USE SIGNAL ;
    PORT
      LAYER met2 ;
        RECT 108.190 396.000 108.470 400.000 ;
    END
  END tex_mport_i[28]
  PIN tex_mport_i[29]
    DIRECTION INPUT ;
    USE SIGNAL ;
    PORT
      LAYER met2 ;
        RECT 110.950 396.000 111.230 400.000 ;
    END
  END tex_mport_i[29]
  PIN tex_mport_i[2]
    DIRECTION INPUT ;
    USE SIGNAL ;
    ANTENNAGATEAREA 0.126000 ;
    PORT
      LAYER met2 ;
        RECT 36.430 396.000 36.710 400.000 ;
    END
  END tex_mport_i[2]
  PIN tex_mport_i[30]
    DIRECTION INPUT ;
    USE SIGNAL ;
    PORT
      LAYER met2 ;
        RECT 113.710 396.000 113.990 400.000 ;
    END
  END tex_mport_i[30]
  PIN tex_mport_i[31]
    DIRECTION INPUT ;
    USE SIGNAL ;
    PORT
      LAYER met2 ;
        RECT 116.470 396.000 116.750 400.000 ;
    END
  END tex_mport_i[31]
  PIN tex_mport_i[32]
    DIRECTION INPUT ;
    USE SIGNAL ;
    ANTENNAGATEAREA 0.868500 ;
    PORT
      LAYER met2 ;
        RECT 119.230 396.000 119.510 400.000 ;
    END
  END tex_mport_i[32]
  PIN tex_mport_i[33]
    DIRECTION INPUT ;
    USE SIGNAL ;
    PORT
      LAYER met2 ;
        RECT 121.990 396.000 122.270 400.000 ;
    END
  END tex_mport_i[33]
  PIN tex_mport_i[3]
    DIRECTION INPUT ;
    USE SIGNAL ;
    ANTENNAGATEAREA 0.126000 ;
    PORT
      LAYER met2 ;
        RECT 39.190 396.000 39.470 400.000 ;
    END
  END tex_mport_i[3]
  PIN tex_mport_i[4]
    DIRECTION INPUT ;
    USE SIGNAL ;
    ANTENNAGATEAREA 0.126000 ;
    PORT
      LAYER met2 ;
        RECT 41.950 396.000 42.230 400.000 ;
    END
  END tex_mport_i[4]
  PIN tex_mport_i[5]
    DIRECTION INPUT ;
    USE SIGNAL ;
    ANTENNAGATEAREA 0.126000 ;
    PORT
      LAYER met2 ;
        RECT 44.710 396.000 44.990 400.000 ;
    END
  END tex_mport_i[5]
  PIN tex_mport_i[6]
    DIRECTION INPUT ;
    USE SIGNAL ;
    ANTENNAGATEAREA 0.126000 ;
    PORT
      LAYER met2 ;
        RECT 47.470 396.000 47.750 400.000 ;
    END
  END tex_mport_i[6]
  PIN tex_mport_i[7]
    DIRECTION INPUT ;
    USE SIGNAL ;
    ANTENNAGATEAREA 0.126000 ;
    PORT
      LAYER met2 ;
        RECT 50.230 396.000 50.510 400.000 ;
    END
  END tex_mport_i[7]
  PIN tex_mport_i[8]
    DIRECTION INPUT ;
    USE SIGNAL ;
    PORT
      LAYER met2 ;
        RECT 52.990 396.000 53.270 400.000 ;
    END
  END tex_mport_i[8]
  PIN tex_mport_i[9]
    DIRECTION INPUT ;
    USE SIGNAL ;
    PORT
      LAYER met2 ;
        RECT 55.750 396.000 56.030 400.000 ;
    END
  END tex_mport_i[9]
  PIN tex_mport_o[0]
    DIRECTION OUTPUT TRISTATE ;
    USE SIGNAL ;
    PORT
      LAYER met2 ;
        RECT 31.370 396.000 31.650 400.000 ;
    END
  END tex_mport_o[0]
  PIN tex_mport_o[10]
    DIRECTION OUTPUT TRISTATE ;
    USE SIGNAL ;
    PORT
      LAYER met2 ;
        RECT 58.970 396.000 59.250 400.000 ;
    END
  END tex_mport_o[10]
  PIN tex_mport_o[11]
    DIRECTION OUTPUT TRISTATE ;
    USE SIGNAL ;
    PORT
      LAYER met2 ;
        RECT 61.730 396.000 62.010 400.000 ;
    END
  END tex_mport_o[11]
  PIN tex_mport_o[12]
    DIRECTION OUTPUT TRISTATE ;
    USE SIGNAL ;
    PORT
      LAYER met2 ;
        RECT 64.490 396.000 64.770 400.000 ;
    END
  END tex_mport_o[12]
  PIN tex_mport_o[13]
    DIRECTION OUTPUT TRISTATE ;
    USE SIGNAL ;
    PORT
      LAYER met2 ;
        RECT 67.250 396.000 67.530 400.000 ;
    END
  END tex_mport_o[13]
  PIN tex_mport_o[14]
    DIRECTION OUTPUT TRISTATE ;
    USE SIGNAL ;
    PORT
      LAYER met2 ;
        RECT 70.010 396.000 70.290 400.000 ;
    END
  END tex_mport_o[14]
  PIN tex_mport_o[15]
    DIRECTION OUTPUT TRISTATE ;
    USE SIGNAL ;
    PORT
      LAYER met2 ;
        RECT 72.770 396.000 73.050 400.000 ;
    END
  END tex_mport_o[15]
  PIN tex_mport_o[16]
    DIRECTION OUTPUT TRISTATE ;
    USE SIGNAL ;
    PORT
      LAYER met2 ;
        RECT 75.530 396.000 75.810 400.000 ;
    END
  END tex_mport_o[16]
  PIN tex_mport_o[17]
    DIRECTION OUTPUT TRISTATE ;
    USE SIGNAL ;
    PORT
      LAYER met2 ;
        RECT 78.290 396.000 78.570 400.000 ;
    END
  END tex_mport_o[17]
  PIN tex_mport_o[18]
    DIRECTION OUTPUT TRISTATE ;
    USE SIGNAL ;
    PORT
      LAYER met2 ;
        RECT 81.050 396.000 81.330 400.000 ;
    END
  END tex_mport_o[18]
  PIN tex_mport_o[19]
    DIRECTION OUTPUT TRISTATE ;
    USE SIGNAL ;
    PORT
      LAYER met2 ;
        RECT 83.810 396.000 84.090 400.000 ;
    END
  END tex_mport_o[19]
  PIN tex_mport_o[1]
    DIRECTION OUTPUT TRISTATE ;
    USE SIGNAL ;
    PORT
      LAYER met2 ;
        RECT 34.130 396.000 34.410 400.000 ;
    END
  END tex_mport_o[1]
  PIN tex_mport_o[20]
    DIRECTION OUTPUT TRISTATE ;
    USE SIGNAL ;
    PORT
      LAYER met2 ;
        RECT 86.570 396.000 86.850 400.000 ;
    END
  END tex_mport_o[20]
  PIN tex_mport_o[21]
    DIRECTION OUTPUT TRISTATE ;
    USE SIGNAL ;
    PORT
      LAYER met2 ;
        RECT 89.330 396.000 89.610 400.000 ;
    END
  END tex_mport_o[21]
  PIN tex_mport_o[22]
    DIRECTION OUTPUT TRISTATE ;
    USE SIGNAL ;
    PORT
      LAYER met2 ;
        RECT 92.090 396.000 92.370 400.000 ;
    END
  END tex_mport_o[22]
  PIN tex_mport_o[23]
    DIRECTION OUTPUT TRISTATE ;
    USE SIGNAL ;
    PORT
      LAYER met2 ;
        RECT 94.850 396.000 95.130 400.000 ;
    END
  END tex_mport_o[23]
  PIN tex_mport_o[24]
    DIRECTION OUTPUT TRISTATE ;
    USE SIGNAL ;
    PORT
      LAYER met2 ;
        RECT 97.610 396.000 97.890 400.000 ;
    END
  END tex_mport_o[24]
  PIN tex_mport_o[25]
    DIRECTION OUTPUT TRISTATE ;
    USE SIGNAL ;
    PORT
      LAYER met2 ;
        RECT 100.370 396.000 100.650 400.000 ;
    END
  END tex_mport_o[25]
  PIN tex_mport_o[26]
    DIRECTION OUTPUT TRISTATE ;
    USE SIGNAL ;
    PORT
      LAYER met2 ;
        RECT 103.130 396.000 103.410 400.000 ;
    END
  END tex_mport_o[26]
  PIN tex_mport_o[27]
    DIRECTION OUTPUT TRISTATE ;
    USE SIGNAL ;
    PORT
      LAYER met2 ;
        RECT 105.890 396.000 106.170 400.000 ;
    END
  END tex_mport_o[27]
  PIN tex_mport_o[28]
    DIRECTION OUTPUT TRISTATE ;
    USE SIGNAL ;
    PORT
      LAYER met2 ;
        RECT 108.650 396.000 108.930 400.000 ;
    END
  END tex_mport_o[28]
  PIN tex_mport_o[29]
    DIRECTION OUTPUT TRISTATE ;
    USE SIGNAL ;
    PORT
      LAYER met2 ;
        RECT 111.410 396.000 111.690 400.000 ;
    END
  END tex_mport_o[29]
  PIN tex_mport_o[2]
    DIRECTION OUTPUT TRISTATE ;
    USE SIGNAL ;
    PORT
      LAYER met2 ;
        RECT 36.890 396.000 37.170 400.000 ;
    END
  END tex_mport_o[2]
  PIN tex_mport_o[30]
    DIRECTION OUTPUT TRISTATE ;
    USE SIGNAL ;
    PORT
      LAYER met2 ;
        RECT 114.170 396.000 114.450 400.000 ;
    END
  END tex_mport_o[30]
  PIN tex_mport_o[31]
    DIRECTION OUTPUT TRISTATE ;
    USE SIGNAL ;
    PORT
      LAYER met2 ;
        RECT 116.930 396.000 117.210 400.000 ;
    END
  END tex_mport_o[31]
  PIN tex_mport_o[32]
    DIRECTION OUTPUT TRISTATE ;
    USE SIGNAL ;
    ANTENNAGATEAREA 0.247500 ;
    ANTENNADIFFAREA 0.891000 ;
    PORT
      LAYER met2 ;
        RECT 119.690 396.000 119.970 400.000 ;
    END
  END tex_mport_o[32]
  PIN tex_mport_o[33]
    DIRECTION OUTPUT TRISTATE ;
    USE SIGNAL ;
    ANTENNAGATEAREA 0.247500 ;
    ANTENNADIFFAREA 0.891000 ;
    PORT
      LAYER met2 ;
        RECT 122.450 396.000 122.730 400.000 ;
    END
  END tex_mport_o[33]
  PIN tex_mport_o[34]
    DIRECTION OUTPUT TRISTATE ;
    USE SIGNAL ;
    ANTENNAGATEAREA 0.247500 ;
    ANTENNADIFFAREA 0.891000 ;
    PORT
      LAYER met2 ;
        RECT 123.830 396.000 124.110 400.000 ;
    END
  END tex_mport_o[34]
  PIN tex_mport_o[35]
    DIRECTION OUTPUT TRISTATE ;
    USE SIGNAL ;
    ANTENNAGATEAREA 0.247500 ;
    ANTENNADIFFAREA 0.891000 ;
    PORT
      LAYER met2 ;
        RECT 125.210 396.000 125.490 400.000 ;
    END
  END tex_mport_o[35]
  PIN tex_mport_o[36]
    DIRECTION OUTPUT TRISTATE ;
    USE SIGNAL ;
    ANTENNAGATEAREA 0.247500 ;
    ANTENNADIFFAREA 0.891000 ;
    PORT
      LAYER met2 ;
        RECT 126.590 396.000 126.870 400.000 ;
    END
  END tex_mport_o[36]
  PIN tex_mport_o[37]
    DIRECTION OUTPUT TRISTATE ;
    USE SIGNAL ;
    ANTENNAGATEAREA 0.126000 ;
    ANTENNADIFFAREA 0.891000 ;
    PORT
      LAYER met2 ;
        RECT 127.970 396.000 128.250 400.000 ;
    END
  END tex_mport_o[37]
  PIN tex_mport_o[38]
    DIRECTION OUTPUT TRISTATE ;
    USE SIGNAL ;
    ANTENNAGATEAREA 0.126000 ;
    ANTENNADIFFAREA 0.891000 ;
    PORT
      LAYER met2 ;
        RECT 129.350 396.000 129.630 400.000 ;
    END
  END tex_mport_o[38]
  PIN tex_mport_o[39]
    DIRECTION OUTPUT TRISTATE ;
    USE SIGNAL ;
    ANTENNAGATEAREA 0.126000 ;
    ANTENNADIFFAREA 0.891000 ;
    PORT
      LAYER met2 ;
        RECT 130.730 396.000 131.010 400.000 ;
    END
  END tex_mport_o[39]
  PIN tex_mport_o[3]
    DIRECTION OUTPUT TRISTATE ;
    USE SIGNAL ;
    PORT
      LAYER met2 ;
        RECT 39.650 396.000 39.930 400.000 ;
    END
  END tex_mport_o[3]
  PIN tex_mport_o[40]
    DIRECTION OUTPUT TRISTATE ;
    USE SIGNAL ;
    ANTENNAGATEAREA 0.126000 ;
    ANTENNADIFFAREA 0.891000 ;
    PORT
      LAYER met2 ;
        RECT 132.110 396.000 132.390 400.000 ;
    END
  END tex_mport_o[40]
  PIN tex_mport_o[41]
    DIRECTION OUTPUT TRISTATE ;
    USE SIGNAL ;
    ANTENNAGATEAREA 0.126000 ;
    ANTENNADIFFAREA 0.891000 ;
    PORT
      LAYER met2 ;
        RECT 133.490 396.000 133.770 400.000 ;
    END
  END tex_mport_o[41]
  PIN tex_mport_o[42]
    DIRECTION OUTPUT TRISTATE ;
    USE SIGNAL ;
    ANTENNAGATEAREA 0.247500 ;
    ANTENNADIFFAREA 0.891000 ;
    PORT
      LAYER met2 ;
        RECT 134.870 396.000 135.150 400.000 ;
    END
  END tex_mport_o[42]
  PIN tex_mport_o[43]
    DIRECTION OUTPUT TRISTATE ;
    USE SIGNAL ;
    ANTENNAGATEAREA 0.126000 ;
    ANTENNADIFFAREA 0.891000 ;
    PORT
      LAYER met2 ;
        RECT 136.250 396.000 136.530 400.000 ;
    END
  END tex_mport_o[43]
  PIN tex_mport_o[44]
    DIRECTION OUTPUT TRISTATE ;
    USE SIGNAL ;
    ANTENNAGATEAREA 0.126000 ;
    ANTENNADIFFAREA 0.891000 ;
    PORT
      LAYER met2 ;
        RECT 137.630 396.000 137.910 400.000 ;
    END
  END tex_mport_o[44]
  PIN tex_mport_o[45]
    DIRECTION OUTPUT TRISTATE ;
    USE SIGNAL ;
    ANTENNAGATEAREA 0.126000 ;
    ANTENNADIFFAREA 0.891000 ;
    PORT
      LAYER met2 ;
        RECT 139.010 396.000 139.290 400.000 ;
    END
  END tex_mport_o[45]
  PIN tex_mport_o[46]
    DIRECTION OUTPUT TRISTATE ;
    USE SIGNAL ;
    ANTENNAGATEAREA 0.126000 ;
    ANTENNADIFFAREA 0.891000 ;
    PORT
      LAYER met2 ;
        RECT 140.390 396.000 140.670 400.000 ;
    END
  END tex_mport_o[46]
  PIN tex_mport_o[47]
    DIRECTION OUTPUT TRISTATE ;
    USE SIGNAL ;
    ANTENNAGATEAREA 0.126000 ;
    ANTENNADIFFAREA 0.891000 ;
    PORT
      LAYER met2 ;
        RECT 141.770 396.000 142.050 400.000 ;
    END
  END tex_mport_o[47]
  PIN tex_mport_o[48]
    DIRECTION OUTPUT TRISTATE ;
    USE SIGNAL ;
    ANTENNAGATEAREA 0.126000 ;
    ANTENNADIFFAREA 0.891000 ;
    PORT
      LAYER met2 ;
        RECT 143.150 396.000 143.430 400.000 ;
    END
  END tex_mport_o[48]
  PIN tex_mport_o[49]
    DIRECTION OUTPUT TRISTATE ;
    USE SIGNAL ;
    ANTENNAGATEAREA 0.126000 ;
    ANTENNADIFFAREA 0.891000 ;
    PORT
      LAYER met2 ;
        RECT 144.530 396.000 144.810 400.000 ;
    END
  END tex_mport_o[49]
  PIN tex_mport_o[4]
    DIRECTION OUTPUT TRISTATE ;
    USE SIGNAL ;
    PORT
      LAYER met2 ;
        RECT 42.410 396.000 42.690 400.000 ;
    END
  END tex_mport_o[4]
  PIN tex_mport_o[50]
    DIRECTION OUTPUT TRISTATE ;
    USE SIGNAL ;
    ANTENNAGATEAREA 0.247500 ;
    ANTENNADIFFAREA 0.891000 ;
    PORT
      LAYER met2 ;
        RECT 145.910 396.000 146.190 400.000 ;
    END
  END tex_mport_o[50]
  PIN tex_mport_o[51]
    DIRECTION OUTPUT TRISTATE ;
    USE SIGNAL ;
    ANTENNAGATEAREA 0.126000 ;
    ANTENNADIFFAREA 0.891000 ;
    PORT
      LAYER met2 ;
        RECT 147.290 396.000 147.570 400.000 ;
    END
  END tex_mport_o[51]
  PIN tex_mport_o[52]
    DIRECTION OUTPUT TRISTATE ;
    USE SIGNAL ;
    ANTENNAGATEAREA 0.126000 ;
    ANTENNADIFFAREA 0.891000 ;
    PORT
      LAYER met2 ;
        RECT 148.670 396.000 148.950 400.000 ;
    END
  END tex_mport_o[52]
  PIN tex_mport_o[53]
    DIRECTION OUTPUT TRISTATE ;
    USE SIGNAL ;
    ANTENNAGATEAREA 0.126000 ;
    ANTENNADIFFAREA 0.891000 ;
    PORT
      LAYER met2 ;
        RECT 150.050 396.000 150.330 400.000 ;
    END
  END tex_mport_o[53]
  PIN tex_mport_o[54]
    DIRECTION OUTPUT TRISTATE ;
    USE SIGNAL ;
    ANTENNAGATEAREA 0.247500 ;
    ANTENNADIFFAREA 0.891000 ;
    PORT
      LAYER met2 ;
        RECT 151.430 396.000 151.710 400.000 ;
    END
  END tex_mport_o[54]
  PIN tex_mport_o[55]
    DIRECTION OUTPUT TRISTATE ;
    USE SIGNAL ;
    ANTENNAGATEAREA 0.126000 ;
    ANTENNADIFFAREA 0.891000 ;
    PORT
      LAYER met2 ;
        RECT 152.810 396.000 153.090 400.000 ;
    END
  END tex_mport_o[55]
  PIN tex_mport_o[56]
    DIRECTION OUTPUT TRISTATE ;
    USE SIGNAL ;
    ANTENNAGATEAREA 0.247500 ;
    ANTENNADIFFAREA 0.891000 ;
    PORT
      LAYER met2 ;
        RECT 154.190 396.000 154.470 400.000 ;
    END
  END tex_mport_o[56]
  PIN tex_mport_o[57]
    DIRECTION OUTPUT TRISTATE ;
    USE SIGNAL ;
    ANTENNAGATEAREA 0.126000 ;
    ANTENNADIFFAREA 0.891000 ;
    PORT
      LAYER met2 ;
        RECT 155.570 396.000 155.850 400.000 ;
    END
  END tex_mport_o[57]
  PIN tex_mport_o[58]
    DIRECTION OUTPUT TRISTATE ;
    USE SIGNAL ;
    ANTENNAGATEAREA 0.247500 ;
    ANTENNADIFFAREA 0.891000 ;
    PORT
      LAYER met2 ;
        RECT 156.950 396.000 157.230 400.000 ;
    END
  END tex_mport_o[58]
  PIN tex_mport_o[59]
    DIRECTION OUTPUT TRISTATE ;
    USE SIGNAL ;
    ANTENNAGATEAREA 0.126000 ;
    ANTENNADIFFAREA 0.891000 ;
    PORT
      LAYER met2 ;
        RECT 158.330 396.000 158.610 400.000 ;
    END
  END tex_mport_o[59]
  PIN tex_mport_o[5]
    DIRECTION OUTPUT TRISTATE ;
    USE SIGNAL ;
    PORT
      LAYER met2 ;
        RECT 45.170 396.000 45.450 400.000 ;
    END
  END tex_mport_o[5]
  PIN tex_mport_o[60]
    DIRECTION OUTPUT TRISTATE ;
    USE SIGNAL ;
    ANTENNAGATEAREA 0.126000 ;
    ANTENNADIFFAREA 0.891000 ;
    PORT
      LAYER met2 ;
        RECT 159.710 396.000 159.990 400.000 ;
    END
  END tex_mport_o[60]
  PIN tex_mport_o[61]
    DIRECTION OUTPUT TRISTATE ;
    USE SIGNAL ;
    ANTENNAGATEAREA 0.126000 ;
    ANTENNADIFFAREA 0.891000 ;
    PORT
      LAYER met2 ;
        RECT 161.090 396.000 161.370 400.000 ;
    END
  END tex_mport_o[61]
  PIN tex_mport_o[62]
    DIRECTION OUTPUT TRISTATE ;
    USE SIGNAL ;
    ANTENNAGATEAREA 0.247500 ;
    ANTENNADIFFAREA 0.891000 ;
    PORT
      LAYER met2 ;
        RECT 162.470 396.000 162.750 400.000 ;
    END
  END tex_mport_o[62]
  PIN tex_mport_o[63]
    DIRECTION OUTPUT TRISTATE ;
    USE SIGNAL ;
    ANTENNAGATEAREA 0.126000 ;
    ANTENNADIFFAREA 0.891000 ;
    PORT
      LAYER met2 ;
        RECT 163.850 396.000 164.130 400.000 ;
    END
  END tex_mport_o[63]
  PIN tex_mport_o[64]
    DIRECTION OUTPUT TRISTATE ;
    USE SIGNAL ;
    ANTENNAGATEAREA 0.126000 ;
    ANTENNADIFFAREA 0.891000 ;
    PORT
      LAYER met2 ;
        RECT 165.230 396.000 165.510 400.000 ;
    END
  END tex_mport_o[64]
  PIN tex_mport_o[65]
    DIRECTION OUTPUT TRISTATE ;
    USE SIGNAL ;
    PORT
      LAYER met2 ;
        RECT 166.610 396.000 166.890 400.000 ;
    END
  END tex_mport_o[65]
  PIN tex_mport_o[66]
    DIRECTION OUTPUT TRISTATE ;
    USE SIGNAL ;
    PORT
      LAYER met2 ;
        RECT 167.990 396.000 168.270 400.000 ;
    END
  END tex_mport_o[66]
  PIN tex_mport_o[67]
    DIRECTION OUTPUT TRISTATE ;
    USE SIGNAL ;
    PORT
      LAYER met2 ;
        RECT 169.370 396.000 169.650 400.000 ;
    END
  END tex_mport_o[67]
  PIN tex_mport_o[68]
    DIRECTION OUTPUT TRISTATE ;
    USE SIGNAL ;
    PORT
      LAYER met2 ;
        RECT 170.750 396.000 171.030 400.000 ;
    END
  END tex_mport_o[68]
  PIN tex_mport_o[6]
    DIRECTION OUTPUT TRISTATE ;
    USE SIGNAL ;
    PORT
      LAYER met2 ;
        RECT 47.930 396.000 48.210 400.000 ;
    END
  END tex_mport_o[6]
  PIN tex_mport_o[7]
    DIRECTION OUTPUT TRISTATE ;
    USE SIGNAL ;
    PORT
      LAYER met2 ;
        RECT 50.690 396.000 50.970 400.000 ;
    END
  END tex_mport_o[7]
  PIN tex_mport_o[8]
    DIRECTION OUTPUT TRISTATE ;
    USE SIGNAL ;
    PORT
      LAYER met2 ;
        RECT 53.450 396.000 53.730 400.000 ;
    END
  END tex_mport_o[8]
  PIN tex_mport_o[9]
    DIRECTION OUTPUT TRISTATE ;
    USE SIGNAL ;
    PORT
      LAYER met2 ;
        RECT 56.210 396.000 56.490 400.000 ;
    END
  END tex_mport_o[9]
  PIN tex_width_i[0]
    DIRECTION INPUT ;
    USE SIGNAL ;
    ANTENNAGATEAREA 0.460500 ;
    ANTENNADIFFAREA 0.869400 ;
    PORT
      LAYER met2 ;
        RECT 109.570 0.000 109.850 4.000 ;
    END
  END tex_width_i[0]
  PIN tex_width_i[10]
    DIRECTION INPUT ;
    USE SIGNAL ;
    ANTENNAGATEAREA 0.247500 ;
    PORT
      LAYER met2 ;
        RECT 137.170 0.000 137.450 4.000 ;
    END
  END tex_width_i[10]
  PIN tex_width_i[11]
    DIRECTION INPUT ;
    USE SIGNAL ;
    ANTENNAGATEAREA 0.247500 ;
    PORT
      LAYER met2 ;
        RECT 139.930 0.000 140.210 4.000 ;
    END
  END tex_width_i[11]
  PIN tex_width_i[12]
    DIRECTION INPUT ;
    USE SIGNAL ;
    ANTENNAGATEAREA 0.247500 ;
    PORT
      LAYER met2 ;
        RECT 142.690 0.000 142.970 4.000 ;
    END
  END tex_width_i[12]
  PIN tex_width_i[13]
    DIRECTION INPUT ;
    USE SIGNAL ;
    ANTENNAGATEAREA 0.552000 ;
    ANTENNADIFFAREA 0.869400 ;
    PORT
      LAYER met2 ;
        RECT 145.450 0.000 145.730 4.000 ;
    END
  END tex_width_i[13]
  PIN tex_width_i[14]
    DIRECTION INPUT ;
    USE SIGNAL ;
    ANTENNAGATEAREA 0.247500 ;
    PORT
      LAYER met2 ;
        RECT 148.210 0.000 148.490 4.000 ;
    END
  END tex_width_i[14]
  PIN tex_width_i[15]
    DIRECTION INPUT ;
    USE SIGNAL ;
    ANTENNAGATEAREA 2.601000 ;
    PORT
      LAYER met2 ;
        RECT 150.970 0.000 151.250 4.000 ;
    END
  END tex_width_i[15]
  PIN tex_width_i[1]
    DIRECTION INPUT ;
    USE SIGNAL ;
    ANTENNAGATEAREA 0.460500 ;
    ANTENNADIFFAREA 0.869400 ;
    PORT
      LAYER met2 ;
        RECT 112.330 0.000 112.610 4.000 ;
    END
  END tex_width_i[1]
  PIN tex_width_i[2]
    DIRECTION INPUT ;
    USE SIGNAL ;
    ANTENNAGATEAREA 0.426000 ;
    ANTENNADIFFAREA 0.434700 ;
    PORT
      LAYER met2 ;
        RECT 115.090 0.000 115.370 4.000 ;
    END
  END tex_width_i[2]
  PIN tex_width_i[3]
    DIRECTION INPUT ;
    USE SIGNAL ;
    ANTENNAGATEAREA 0.213000 ;
    PORT
      LAYER met2 ;
        RECT 117.850 0.000 118.130 4.000 ;
    END
  END tex_width_i[3]
  PIN tex_width_i[4]
    DIRECTION INPUT ;
    USE SIGNAL ;
    ANTENNAGATEAREA 0.247500 ;
    PORT
      LAYER met2 ;
        RECT 120.610 0.000 120.890 4.000 ;
    END
  END tex_width_i[4]
  PIN tex_width_i[5]
    DIRECTION INPUT ;
    USE SIGNAL ;
    ANTENNAGATEAREA 1.644000 ;
    PORT
      LAYER met2 ;
        RECT 123.370 0.000 123.650 4.000 ;
    END
  END tex_width_i[5]
  PIN tex_width_i[6]
    DIRECTION INPUT ;
    USE SIGNAL ;
    ANTENNAGATEAREA 1.258500 ;
    PORT
      LAYER met2 ;
        RECT 126.130 0.000 126.410 4.000 ;
    END
  END tex_width_i[6]
  PIN tex_width_i[7]
    DIRECTION INPUT ;
    USE SIGNAL ;
    ANTENNAGATEAREA 0.495000 ;
    ANTENNADIFFAREA 0.434700 ;
    PORT
      LAYER met2 ;
        RECT 128.890 0.000 129.170 4.000 ;
    END
  END tex_width_i[7]
  PIN tex_width_i[8]
    DIRECTION INPUT ;
    USE SIGNAL ;
    ANTENNAGATEAREA 0.495000 ;
    PORT
      LAYER met2 ;
        RECT 131.650 0.000 131.930 4.000 ;
    END
  END tex_width_i[8]
  PIN tex_width_i[9]
    DIRECTION INPUT ;
    USE SIGNAL ;
    ANTENNAGATEAREA 0.708000 ;
    PORT
      LAYER met2 ;
        RECT 134.410 0.000 134.690 4.000 ;
    END
  END tex_width_i[9]
  PIN vccd1
    DIRECTION INOUT ;
    USE POWER ;
    PORT
      LAYER met4 ;
        RECT 21.040 10.640 22.640 389.200 ;
    END
    PORT
      LAYER met4 ;
        RECT 174.640 10.640 176.240 389.200 ;
    END
  END vccd1
  PIN vssd1
    DIRECTION INOUT ;
    USE GROUND ;
    PORT
      LAYER met4 ;
        RECT 97.840 10.640 99.440 389.200 ;
    END
  END vssd1
  OBS
      LAYER li1 ;
        RECT 5.520 10.795 194.120 389.045 ;
      LAYER met1 ;
        RECT 0.990 7.180 195.430 391.640 ;
      LAYER met2 ;
        RECT 1.020 395.720 28.790 396.000 ;
        RECT 171.310 395.720 195.400 396.000 ;
        RECT 1.020 4.280 195.400 395.720 ;
        RECT 1.020 3.670 4.410 4.280 ;
        RECT 5.250 3.670 7.170 4.280 ;
        RECT 8.010 3.670 9.930 4.280 ;
        RECT 10.770 3.670 12.690 4.280 ;
        RECT 13.530 3.670 15.450 4.280 ;
        RECT 16.290 3.670 18.210 4.280 ;
        RECT 19.050 3.670 20.970 4.280 ;
        RECT 21.810 3.670 23.730 4.280 ;
        RECT 24.570 3.670 26.490 4.280 ;
        RECT 27.330 3.670 29.250 4.280 ;
        RECT 30.090 3.670 32.010 4.280 ;
        RECT 32.850 3.670 34.770 4.280 ;
        RECT 35.610 3.670 37.530 4.280 ;
        RECT 38.370 3.670 40.290 4.280 ;
        RECT 41.130 3.670 43.050 4.280 ;
        RECT 43.890 3.670 45.810 4.280 ;
        RECT 46.650 3.670 48.570 4.280 ;
        RECT 49.410 3.670 51.330 4.280 ;
        RECT 52.170 3.670 54.090 4.280 ;
        RECT 54.930 3.670 56.850 4.280 ;
        RECT 57.690 3.670 59.610 4.280 ;
        RECT 60.450 3.670 62.370 4.280 ;
        RECT 63.210 3.670 65.130 4.280 ;
        RECT 65.970 3.670 67.890 4.280 ;
        RECT 68.730 3.670 70.650 4.280 ;
        RECT 71.490 3.670 73.410 4.280 ;
        RECT 74.250 3.670 76.170 4.280 ;
        RECT 77.010 3.670 78.930 4.280 ;
        RECT 79.770 3.670 81.690 4.280 ;
        RECT 82.530 3.670 84.450 4.280 ;
        RECT 85.290 3.670 87.210 4.280 ;
        RECT 88.050 3.670 89.970 4.280 ;
        RECT 90.810 3.670 92.730 4.280 ;
        RECT 93.570 3.670 95.490 4.280 ;
        RECT 96.330 3.670 98.250 4.280 ;
        RECT 99.090 3.670 101.010 4.280 ;
        RECT 101.850 3.670 103.770 4.280 ;
        RECT 104.610 3.670 106.530 4.280 ;
        RECT 107.370 3.670 109.290 4.280 ;
        RECT 110.130 3.670 112.050 4.280 ;
        RECT 112.890 3.670 114.810 4.280 ;
        RECT 115.650 3.670 117.570 4.280 ;
        RECT 118.410 3.670 120.330 4.280 ;
        RECT 121.170 3.670 123.090 4.280 ;
        RECT 123.930 3.670 125.850 4.280 ;
        RECT 126.690 3.670 128.610 4.280 ;
        RECT 129.450 3.670 131.370 4.280 ;
        RECT 132.210 3.670 134.130 4.280 ;
        RECT 134.970 3.670 136.890 4.280 ;
        RECT 137.730 3.670 139.650 4.280 ;
        RECT 140.490 3.670 142.410 4.280 ;
        RECT 143.250 3.670 145.170 4.280 ;
        RECT 146.010 3.670 147.930 4.280 ;
        RECT 148.770 3.670 150.690 4.280 ;
        RECT 151.530 3.670 153.450 4.280 ;
        RECT 154.290 3.670 156.210 4.280 ;
        RECT 157.050 3.670 158.970 4.280 ;
        RECT 159.810 3.670 161.730 4.280 ;
        RECT 162.570 3.670 164.490 4.280 ;
        RECT 165.330 3.670 167.250 4.280 ;
        RECT 168.090 3.670 170.010 4.280 ;
        RECT 170.850 3.670 172.770 4.280 ;
        RECT 173.610 3.670 175.530 4.280 ;
        RECT 176.370 3.670 178.290 4.280 ;
        RECT 179.130 3.670 181.050 4.280 ;
        RECT 181.890 3.670 183.810 4.280 ;
        RECT 184.650 3.670 186.570 4.280 ;
        RECT 187.410 3.670 189.330 4.280 ;
        RECT 190.170 3.670 192.090 4.280 ;
        RECT 192.930 3.670 194.850 4.280 ;
      LAYER met3 ;
        RECT 0.270 357.360 189.915 390.145 ;
        RECT 4.400 355.960 189.915 357.360 ;
        RECT 0.270 354.640 189.915 355.960 ;
        RECT 4.400 353.240 189.915 354.640 ;
        RECT 0.270 351.920 189.915 353.240 ;
        RECT 4.400 350.520 189.915 351.920 ;
        RECT 0.270 349.200 189.915 350.520 ;
        RECT 4.400 347.800 189.915 349.200 ;
        RECT 0.270 346.480 189.915 347.800 ;
        RECT 4.400 345.080 189.915 346.480 ;
        RECT 0.270 343.760 189.915 345.080 ;
        RECT 4.400 342.360 189.915 343.760 ;
        RECT 0.270 341.040 189.915 342.360 ;
        RECT 4.400 339.640 189.915 341.040 ;
        RECT 0.270 338.320 189.915 339.640 ;
        RECT 4.400 336.920 189.915 338.320 ;
        RECT 0.270 335.600 189.915 336.920 ;
        RECT 4.400 334.200 189.915 335.600 ;
        RECT 0.270 332.880 189.915 334.200 ;
        RECT 4.400 331.480 189.915 332.880 ;
        RECT 0.270 330.160 189.915 331.480 ;
        RECT 4.400 328.760 189.915 330.160 ;
        RECT 0.270 327.440 189.915 328.760 ;
        RECT 4.400 326.040 189.915 327.440 ;
        RECT 0.270 324.720 189.915 326.040 ;
        RECT 4.400 323.320 189.915 324.720 ;
        RECT 0.270 322.000 189.915 323.320 ;
        RECT 4.400 320.600 189.915 322.000 ;
        RECT 0.270 319.280 189.915 320.600 ;
        RECT 4.400 317.880 189.915 319.280 ;
        RECT 0.270 316.560 189.915 317.880 ;
        RECT 4.400 315.160 189.915 316.560 ;
        RECT 0.270 313.840 189.915 315.160 ;
        RECT 4.400 312.440 189.915 313.840 ;
        RECT 0.270 311.120 189.915 312.440 ;
        RECT 4.400 309.720 189.915 311.120 ;
        RECT 0.270 308.400 189.915 309.720 ;
        RECT 4.400 307.000 189.915 308.400 ;
        RECT 0.270 305.680 189.915 307.000 ;
        RECT 4.400 304.280 189.915 305.680 ;
        RECT 0.270 302.960 189.915 304.280 ;
        RECT 4.400 301.560 189.915 302.960 ;
        RECT 0.270 300.240 189.915 301.560 ;
        RECT 4.400 298.840 189.915 300.240 ;
        RECT 0.270 297.520 189.915 298.840 ;
        RECT 4.400 296.120 189.915 297.520 ;
        RECT 0.270 294.800 189.915 296.120 ;
        RECT 4.400 293.400 189.915 294.800 ;
        RECT 0.270 292.080 189.915 293.400 ;
        RECT 4.400 290.680 189.915 292.080 ;
        RECT 0.270 289.360 189.915 290.680 ;
        RECT 4.400 287.960 189.915 289.360 ;
        RECT 0.270 286.640 189.915 287.960 ;
        RECT 4.400 285.240 189.915 286.640 ;
        RECT 0.270 283.920 189.915 285.240 ;
        RECT 4.400 282.520 189.915 283.920 ;
        RECT 0.270 281.200 189.915 282.520 ;
        RECT 4.400 279.800 189.915 281.200 ;
        RECT 0.270 278.480 189.915 279.800 ;
        RECT 4.400 277.080 189.915 278.480 ;
        RECT 0.270 275.760 189.915 277.080 ;
        RECT 4.400 274.360 189.915 275.760 ;
        RECT 0.270 273.040 189.915 274.360 ;
        RECT 4.400 271.640 189.915 273.040 ;
        RECT 0.270 270.320 189.915 271.640 ;
        RECT 4.400 268.920 189.915 270.320 ;
        RECT 0.270 267.600 189.915 268.920 ;
        RECT 4.400 266.200 189.915 267.600 ;
        RECT 0.270 264.880 189.915 266.200 ;
        RECT 4.400 263.480 189.915 264.880 ;
        RECT 0.270 262.160 189.915 263.480 ;
        RECT 4.400 260.760 189.915 262.160 ;
        RECT 0.270 259.440 189.915 260.760 ;
        RECT 4.400 258.040 189.915 259.440 ;
        RECT 0.270 256.720 189.915 258.040 ;
        RECT 4.400 255.320 189.915 256.720 ;
        RECT 0.270 254.000 189.915 255.320 ;
        RECT 4.400 252.600 189.915 254.000 ;
        RECT 0.270 251.280 189.915 252.600 ;
        RECT 4.400 249.880 189.915 251.280 ;
        RECT 0.270 248.560 189.915 249.880 ;
        RECT 4.400 247.160 189.915 248.560 ;
        RECT 0.270 245.840 189.915 247.160 ;
        RECT 4.400 244.440 189.915 245.840 ;
        RECT 0.270 243.120 189.915 244.440 ;
        RECT 4.400 241.720 189.915 243.120 ;
        RECT 0.270 240.400 189.915 241.720 ;
        RECT 4.400 239.000 189.915 240.400 ;
        RECT 0.270 237.680 189.915 239.000 ;
        RECT 4.400 236.280 189.915 237.680 ;
        RECT 0.270 234.960 189.915 236.280 ;
        RECT 4.400 233.560 189.915 234.960 ;
        RECT 0.270 232.240 189.915 233.560 ;
        RECT 4.400 230.840 189.915 232.240 ;
        RECT 0.270 229.520 189.915 230.840 ;
        RECT 4.400 228.120 189.915 229.520 ;
        RECT 0.270 226.800 189.915 228.120 ;
        RECT 4.400 225.400 189.915 226.800 ;
        RECT 0.270 224.080 189.915 225.400 ;
        RECT 4.400 222.680 189.915 224.080 ;
        RECT 0.270 221.360 189.915 222.680 ;
        RECT 4.400 219.960 189.915 221.360 ;
        RECT 0.270 218.640 189.915 219.960 ;
        RECT 4.400 217.240 189.915 218.640 ;
        RECT 0.270 215.920 189.915 217.240 ;
        RECT 4.400 214.520 189.915 215.920 ;
        RECT 0.270 213.200 189.915 214.520 ;
        RECT 4.400 211.800 189.915 213.200 ;
        RECT 0.270 210.480 189.915 211.800 ;
        RECT 4.400 209.080 189.915 210.480 ;
        RECT 0.270 207.760 189.915 209.080 ;
        RECT 4.400 206.360 189.915 207.760 ;
        RECT 0.270 205.040 189.915 206.360 ;
        RECT 4.400 203.640 189.915 205.040 ;
        RECT 0.270 202.320 189.915 203.640 ;
        RECT 4.400 200.920 189.915 202.320 ;
        RECT 0.270 199.600 189.915 200.920 ;
        RECT 4.400 198.200 189.915 199.600 ;
        RECT 0.270 196.880 189.915 198.200 ;
        RECT 4.400 195.480 189.915 196.880 ;
        RECT 0.270 194.160 189.915 195.480 ;
        RECT 4.400 192.760 189.915 194.160 ;
        RECT 0.270 191.440 189.915 192.760 ;
        RECT 4.400 190.040 189.915 191.440 ;
        RECT 0.270 188.720 189.915 190.040 ;
        RECT 4.400 187.320 189.915 188.720 ;
        RECT 0.270 186.000 189.915 187.320 ;
        RECT 4.400 184.600 189.915 186.000 ;
        RECT 0.270 183.280 189.915 184.600 ;
        RECT 4.400 181.880 189.915 183.280 ;
        RECT 0.270 180.560 189.915 181.880 ;
        RECT 4.400 179.160 189.915 180.560 ;
        RECT 0.270 177.840 189.915 179.160 ;
        RECT 4.400 176.440 189.915 177.840 ;
        RECT 0.270 175.120 189.915 176.440 ;
        RECT 4.400 173.720 189.915 175.120 ;
        RECT 0.270 172.400 189.915 173.720 ;
        RECT 4.400 171.000 189.915 172.400 ;
        RECT 0.270 169.680 189.915 171.000 ;
        RECT 4.400 168.280 189.915 169.680 ;
        RECT 0.270 166.960 189.915 168.280 ;
        RECT 4.400 165.560 189.915 166.960 ;
        RECT 0.270 164.240 189.915 165.560 ;
        RECT 4.400 162.840 189.915 164.240 ;
        RECT 0.270 161.520 189.915 162.840 ;
        RECT 4.400 160.120 189.915 161.520 ;
        RECT 0.270 158.800 189.915 160.120 ;
        RECT 4.400 157.400 189.915 158.800 ;
        RECT 0.270 156.080 189.915 157.400 ;
        RECT 4.400 154.680 189.915 156.080 ;
        RECT 0.270 153.360 189.915 154.680 ;
        RECT 4.400 151.960 189.915 153.360 ;
        RECT 0.270 150.640 189.915 151.960 ;
        RECT 4.400 149.240 189.915 150.640 ;
        RECT 0.270 147.920 189.915 149.240 ;
        RECT 4.400 146.520 189.915 147.920 ;
        RECT 0.270 145.200 189.915 146.520 ;
        RECT 4.400 143.800 189.915 145.200 ;
        RECT 0.270 142.480 189.915 143.800 ;
        RECT 4.400 141.080 189.915 142.480 ;
        RECT 0.270 139.760 189.915 141.080 ;
        RECT 4.400 138.360 189.915 139.760 ;
        RECT 0.270 137.040 189.915 138.360 ;
        RECT 4.400 135.640 189.915 137.040 ;
        RECT 0.270 134.320 189.915 135.640 ;
        RECT 4.400 132.920 189.915 134.320 ;
        RECT 0.270 131.600 189.915 132.920 ;
        RECT 4.400 130.200 189.915 131.600 ;
        RECT 0.270 128.880 189.915 130.200 ;
        RECT 4.400 127.480 189.915 128.880 ;
        RECT 0.270 126.160 189.915 127.480 ;
        RECT 4.400 124.760 189.915 126.160 ;
        RECT 0.270 123.440 189.915 124.760 ;
        RECT 4.400 122.040 189.915 123.440 ;
        RECT 0.270 120.720 189.915 122.040 ;
        RECT 4.400 119.320 189.915 120.720 ;
        RECT 0.270 118.000 189.915 119.320 ;
        RECT 4.400 116.600 189.915 118.000 ;
        RECT 0.270 115.280 189.915 116.600 ;
        RECT 4.400 113.880 189.915 115.280 ;
        RECT 0.270 112.560 189.915 113.880 ;
        RECT 4.400 111.160 189.915 112.560 ;
        RECT 0.270 109.840 189.915 111.160 ;
        RECT 4.400 108.440 189.915 109.840 ;
        RECT 0.270 107.120 189.915 108.440 ;
        RECT 4.400 105.720 189.915 107.120 ;
        RECT 0.270 104.400 189.915 105.720 ;
        RECT 4.400 103.000 189.915 104.400 ;
        RECT 0.270 101.680 189.915 103.000 ;
        RECT 4.400 100.280 189.915 101.680 ;
        RECT 0.270 98.960 189.915 100.280 ;
        RECT 4.400 97.560 189.915 98.960 ;
        RECT 0.270 96.240 189.915 97.560 ;
        RECT 4.400 94.840 189.915 96.240 ;
        RECT 0.270 93.520 189.915 94.840 ;
        RECT 4.400 92.120 189.915 93.520 ;
        RECT 0.270 90.800 189.915 92.120 ;
        RECT 4.400 89.400 189.915 90.800 ;
        RECT 0.270 88.080 189.915 89.400 ;
        RECT 4.400 86.680 189.915 88.080 ;
        RECT 0.270 85.360 189.915 86.680 ;
        RECT 4.400 83.960 189.915 85.360 ;
        RECT 0.270 82.640 189.915 83.960 ;
        RECT 4.400 81.240 189.915 82.640 ;
        RECT 0.270 79.920 189.915 81.240 ;
        RECT 4.400 78.520 189.915 79.920 ;
        RECT 0.270 77.200 189.915 78.520 ;
        RECT 4.400 75.800 189.915 77.200 ;
        RECT 0.270 74.480 189.915 75.800 ;
        RECT 4.400 73.080 189.915 74.480 ;
        RECT 0.270 71.760 189.915 73.080 ;
        RECT 4.400 70.360 189.915 71.760 ;
        RECT 0.270 69.040 189.915 70.360 ;
        RECT 4.400 67.640 189.915 69.040 ;
        RECT 0.270 66.320 189.915 67.640 ;
        RECT 4.400 64.920 189.915 66.320 ;
        RECT 0.270 63.600 189.915 64.920 ;
        RECT 4.400 62.200 189.915 63.600 ;
        RECT 0.270 60.880 189.915 62.200 ;
        RECT 4.400 59.480 189.915 60.880 ;
        RECT 0.270 58.160 189.915 59.480 ;
        RECT 4.400 56.760 189.915 58.160 ;
        RECT 0.270 55.440 189.915 56.760 ;
        RECT 4.400 54.040 189.915 55.440 ;
        RECT 0.270 52.720 189.915 54.040 ;
        RECT 4.400 51.320 189.915 52.720 ;
        RECT 0.270 50.000 189.915 51.320 ;
        RECT 4.400 48.600 189.915 50.000 ;
        RECT 0.270 47.280 189.915 48.600 ;
        RECT 4.400 45.880 189.915 47.280 ;
        RECT 0.270 44.560 189.915 45.880 ;
        RECT 4.400 43.160 189.915 44.560 ;
        RECT 0.270 41.840 189.915 43.160 ;
        RECT 4.400 40.440 189.915 41.840 ;
        RECT 0.270 10.715 189.915 40.440 ;
      LAYER met4 ;
        RECT 0.295 389.600 171.745 390.145 ;
        RECT 0.295 11.735 20.640 389.600 ;
        RECT 23.040 11.735 97.440 389.600 ;
        RECT 99.840 11.735 171.745 389.600 ;
  END
END end_pipe_m
END LIBRARY

